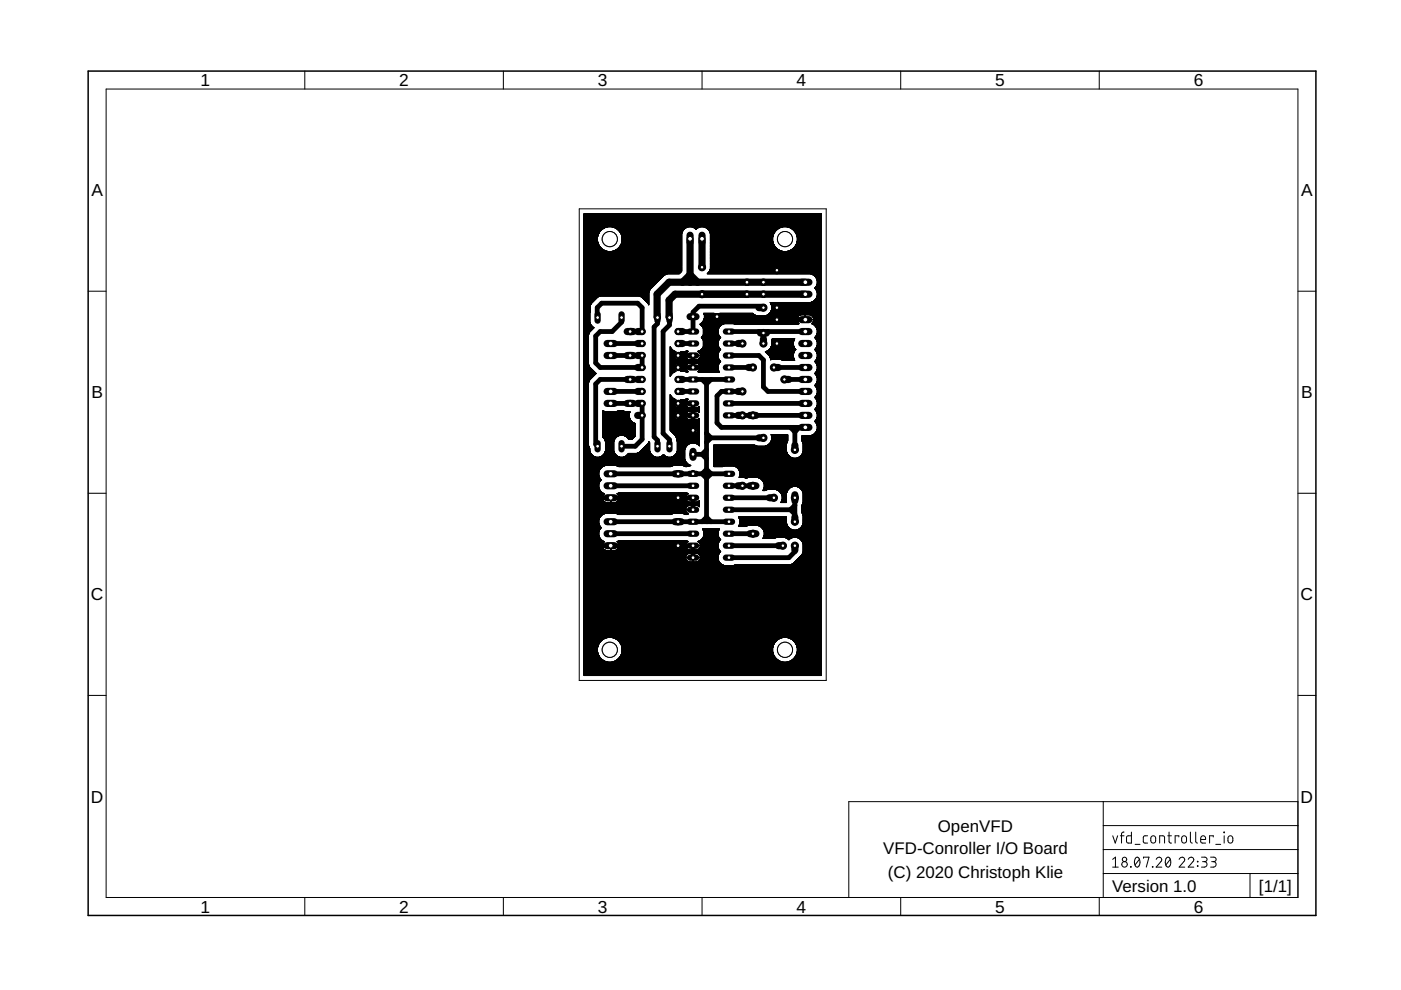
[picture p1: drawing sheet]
<svg xmlns="http://www.w3.org/2000/svg" width="297mm" height="210mm" viewBox="0 0 297 210" stroke-linecap="round" stroke-linejoin="round" font-family="sans-serif">
<defs><g id="words">
<g font-size="3.7">
<text x="42.5" y="18.3">1</text>
<text x="84.7" y="18.3">2</text>
<text x="126.8" y="18.3">3</text>
<text x="168.9" y="18.3">4</text>
<text x="211" y="18.3">5</text>
<text x="253.1" y="18.3">6</text>
<text x="19.4" y="41.6">A</text>
<text x="275.9" y="41.6">A</text>
<text x="19.4" y="84.5">B</text>
<text x="275.9" y="84.5">B</text>
<text x="19.3" y="127.3">C</text>
<text x="275.8" y="127.3">C</text>
<text x="19.3" y="170.2">D</text>
<text x="275.8" y="170.2">D</text>
<text x="42.5" y="193.5">1</text>
<text x="84.7" y="193.5">2</text>
<text x="126.8" y="193.5">3</text>
<text x="168.9" y="193.5">4</text>
<text x="211" y="193.5">5</text>
<text x="253.1" y="193.5">6</text>
</g>
<g font-size="3.6">
<text x="198.8" y="176.3">OpenVFD</text>
<text x="187.3" y="181.1">VFD-Conroller I/O Board</text>
<text x="188.3" y="186.2">(C) 2020 Christoph Klie</text>
<text x="235.8" y="189">Version 1.0</text>
<text x="266.9" y="189">[1/1]</text>
</g>
</g></defs>
<g fill="none" stroke="#000" stroke-width=".51">
<circle cx="129.3" cy="50.7" r=".76"/>
<circle cx="166.4" cy="50.7" r=".76"/>
<circle cx="129.3" cy="137.8" r=".76"/>
<circle cx="166.4" cy="137.8" r=".76"/>
</g>
<g fill="none" stroke="#000" stroke-width="1">
<path d="M164.7 57.3v-.3l-10.8-10.8h-29.6v68.5l1 1h17.8M126.7 67.3l-.1-2.1 1-.9h7.6l.9 .9v5.1M129.5 75.4h3.5M129.5 72.8h5.7M131.8 67.3v1l-2 2h-2.5l-1 .9v5.8l1 .9h7.9M133.9 70.3h1.3M134.2 75.4h1M136.1 75.4v2.5M139.4 67.3v1.3l-.7 .7v23.3l.7 .7v1.3M141.9 67.3v1.6l-1.3 1.4v21.6l1.3 1.3v1.4M144.7 75.4h2.2v2.5M144.7 72.8h2.2"/>
<path d="M151.4 67.8l.6-.7 .7 .7M154.6 70.3h16.2M154.6 75.4h6.3l1 .9v5.7l.9 1h8M154.6 77.9h4.1M154.6 72.8h1.9M160.9 70.3l1 .9M161.9 65.2l-.4-.3h-13.3l-1.3 1.3v4.1h-2.2M161.9 71.2v.7M162.8 70.3l-.9 .9M164.1 67.8h-14l-.6 .6v8.6l-1 .9h-3.8M164.7 66.2v1.6M164.7 66.8l1 1"/>
<path d="M165 77.9h5.8M165.4 67.8h5.4M129.5 85.5h3.5M129.5 83h5.7M133 80.5h-5.7l-1 .9v12.8l.4 .4M134.2 80.5h1M134.2 85.5h1M136.1 85.5v7.7l-1.4 1.4h-2.9M136.1 88.1l.1 .1M144.7 80.5h9.9M144.7 85.5h2.2v5.1M144.7 88.1h2.2"/>
<path d="M144.7 83h2.2M146.9 96.3h1.9M146.9 91.2h-1.5l-1 1v4.1l-1.6 1.6h-18.5M148.8 80.5l1 .9M148.8 96.3l1 1M149.8 81.4v29.2M149.8 99.5l.9 1-.9 .9-1-.9zM149.8 95.4l-1 .9M149.8 91.9l.9 .9M150.7 80.5l-.9 .9M150.7 92.8l-.9 1M150.7 92.8h10.2"/>
<path d="M154.6 88.1h1.9M154.6 85.5h16.2M156.5 83h-3.5l-1 .9v5.8l1 .9h17.8M157.4 88.1h1.6M160.3 88.1h10.5M167.3 80.5h3.5M167.6 90.6l.9 1 1-1M168.2 90.6l.3 .3v3.5M124.3 104.6l1 .9M125.3 105.5h17.8M125.3 105.5l-1 1M129.5 110.6h13.6"/>
<path d="M129.5 100.5h13.6M129.5 103h17.4M129.5 113.2h17.4M144.4 100.5h2.2l.3-.4v.4h7.7M144.4 105.5h2.5v2.6M144.4 115.7h2.5v2.5M144.4 110.6h10.2M148.8 110.6l1-.9 .9 .9M154.6 115.7h10.4M154.6 105.5h8.5M154.6 108.1h13M154.6 103h1.9"/>
<path d="M154.6 113.2h4.4M157.4 103h1.6M167.6 108.1l.9 .9M168.5 116.3v.7l-1.2 1.2h-12.7M168.5 106.2v3.5M168.5 107.1l-.9 1"/>
</g>
<g fill="none" stroke="#000" stroke-width="1.5">
<path d="M144.7 59.8l1.6-1.5 1.6 1.5M146.3 50.6v9.2M148.8 50.6v6.1M170.8 59.8h-28.9l-2.6 2.6 .1 4.9M133 70.3h1.2M133 75.4h1.2M135.2 70.3h.9M135.2 77.9h.9M135.2 75.4h.9M135.2 72.8h.9M143.8 70.3h.9M143.8 77.9h.9"/>
<path d="M143.8 75.4h.9M143.8 72.8h.9M146.3 67.1h1.3M151.4 67.1h1.3M156.5 72.8h.9M158.7 77.9h.9M160.9 65.2h1M161.2 70.6h1.3M161.9 71.9v.9M164.1 77.9h.9M164.1 67.8h1.3M164.7 65.2v1"/>
<path d="M170.8 62.4h-27.7l-1.2 1.2v3.7M133 80.5h1.2M133 85.5h1.2M135.2 80.5h.9M135.2 85.5h.9M135.2 88.1h.9M135.2 83h.9M143.8 80.5h.9M143.8 85.5h.9M143.8 88.1h.9M143.8 83h.9M146.9 90.6v1.3"/>
<path d="M146.9 95.7v1.3M156.5 88.1h.9M156.5 83h.9M159 88.1h1.3M160.9 92.8h1M166.3 80.5h1M168.5 94.4v1M143.1 110.6h1.3M143.1 100.5h1.3M143.1 115.7h1.3M143.1 105.5h1.3M156.5 103h.9"/>
<path d="M159 103h1.3M159 113.2h1.3M163.1 105.5h1M165 115.7h1M168.5 104.9v1.3M168.5 109.7v.9M168.5 115.7v.9"/>
</g>
<g fill="none" stroke="#000" stroke-width=".21">
<path d="M123.8 45.3h50.3v97.9h-50.3zM123.8 53.3h20.7M123.8 57.4h20.7M123.8 57.3h20.7M123.8 57.2h20.7M123.8 57.1h20.7M123.8 57h20.7M123.8 56.9h20.7M123.8 56.8h20.7M123.8 56.7h20.7M123.8 56.6h20.7M123.8 56.5h20.7"/>
<path d="M123.8 56.4h20.7M123.8 56.3h20.7M123.8 56.2h20.7M123.8 56.1h20.7M123.8 56h20.7M123.8 55.9h20.7M123.8 55.8h20.7M123.8 55.7h20.7M123.8 55.6h20.7M123.8 55.5h20.7M123.8 55.4h20.7M123.8 55.3h20.7"/>
<path d="M123.8 55.2h20.7M123.8 55.1h20.7M123.8 55h20.7M123.8 54.9h20.7M123.8 54.8h20.7M123.8 54.7h20.7M123.8 54.6h20.7M123.8 54.5h20.7M123.8 54.4h20.7M123.8 54.3h20.7M123.8 54.2h20.7M123.8 54.1h20.7"/>
<path d="M123.8 54h20.7M123.8 53.9h20.7M123.8 53.8h20.7M123.8 53.7h20.7M123.8 53.6h20.7M123.8 53.5h20.7M123.8 53.4h20.7M123.8 53.3h5M123.8 53.2h4.8M123.8 53.1l4.6 .1M123.8 53.1h4.4M123.8 53l4.3 .1"/>
<path d="M123.8 53h4.3M123.8 52.9l4.2 .1M123.8 52.9h4.1M123.8 52.8l4 .1M123.8 52.8h3.9M123.8 52.7h3.8M123.8 52.6h3.7M123.8 52.5h3.6M123.8 52.4h3.5M123.8 52.3l3.5 .1M123.8 52.3h3.4M123.8 52.2l3.4 .1"/>
<path d="M123.8 52.2h3.3M123.8 52.1l3.3 .1M123.8 52.1h3.3M123.8 52l3.2 .1M123.8 52h3.2M123.8 51.9h3.2M123.8 51.8h3.1M123.8 51.7h3.1M123.8 51.7h3M123.8 51.6h3M123.8 51.5h3M123.8 51.4h3"/>
<path d="M123.8 51.4h2.9M123.8 51.3h2.9M123.8 51.2l2.9 .1M123.8 51.2h2.9M123.8 51.1h2.9M123.8 51h2.9M123.8 50.9h2.9M123.8 50.8h2.9M123.8 50.7h2.9M123.8 50.6h2.9M123.8 50.5h2.9M123.8 50.4h2.9"/>
<path d="M123.8 50.3h2.9M123.8 50.2h2.9M123.8 50.1h2.9M123.8 50h2.9M123.8 49.9h3M123.8 49.8h3M123.8 49.7h3M123.8 49.6h3.1M123.8 48h50.3M123.8 47.9h50.3M123.8 47.8h50.3M123.8 47.7h50.3"/>
<path d="M123.8 47.6h50.3M123.8 47.5h50.3M123.8 47.4h50.3M123.8 47.3h50.3M123.8 47.2h50.3M123.8 47.1h50.3M123.8 47h50.3M123.8 46.9h50.3M123.8 46.8h50.3M123.8 46.7h50.3M123.8 46.6h50.3M123.8 46.5h50.3"/>
<path d="M123.8 46.4h50.3M123.8 46.3h50.3M123.8 46.2h50.3M123.8 46.1h50.3M123.8 46h50.3M123.8 45.9h50.3M123.8 45.8h50.3M123.8 45.7h50.3M123.8 45.6h50.3M123.8 45.5h50.3M123.8 45.4h50.3M126.7 50.4v.7"/>
<path d="M126.7 51.1l.1 .6M126.7 50.3h-2.9M126.7 50.1l-2.9 .1M126.8 50h-3M126.8 49.9h-3M126.8 49.8h-3M126.8 49.7l-.1 .7M126.8 51.7l.4 .6M126.9 49.7h-3.1M126.9 49.6h-3.1M127 49.5h-3.2M127 49.4l-3.2 .1"/>
<path d="M127 49.4h-3.2M127 49.3l-3.2 .1M127.1 49.3h-3.3M127.1 49.2l-3.3 .1M127.1 49.2h-3.3M127.2 49.1h-3.4M127.2 49.1l-.4 .6M127.2 52.3l.5 .5M127.3 49h-3.5M127.4 48.9h-3.6M127.5 48.8h-3.7M127.5 48.7l-3.7 .1"/>
<path d="M127.6 48.7h-3.8M127.6 48.6l-3.8 .1M127.7 48.6l-.5 .5M127.7 52.8l1.2 .5M127.7 48.6h-3.9M127.8 48.5l-4 .1M127.9 48.5h-4.1M128 48.4l-4.2 .1M128.1 48.4h-4.3M128.2 48.3l-4.4 .1M128.2 48.3h-4.4M128.4 48.2l-4.6 .1"/>
<path d="M128.6 48.2h-4.8M128.8 48.1l-5 .1M128.9 48.1l-1.2 .5M129.6 48.1l1.3 .5M129.8 48.1h16.1M129.8 53.3h14.7M130 53.2h14.5M130 48.2h15.7M130.2 48.2h15.4M130.2 53.2h14.3M130.3 53.1h14.2M130.3 48.3h15.2"/>
<path d="M130.4 48.3h15M130.5 53.1h14M130.5 53h14M130.5 48.4h14.8M130.6 48.4h14.6M130.6 53h13.9M130.7 52.9h13.8M130.7 48.5h14.5M130.8 48.5h14.3M130.8 52.9h13.7M130.9 48.6l.8 1.1M130.9 52.8l-1.3 .5"/>
<path d="M130.9 52.8h13.6M130.9 48.6h14.2M130.9 48.6h14.1M131 52.7h13.5M131 48.7h13.9M131.1 52.6h13.4M131.1 48.8h13.7M131.1 48.9h13.7M131.2 52.5h13.3M131.2 48.9h13.6M131.3 49h13.5M131.3 52.4h13.2"/>
<path d="M131.3 49h13.4M131.4 49.1h13.3M131.4 52.3l-.5 .5M131.4 52.3h13.1M131.4 52.2h13.1M131.5 52.2h13M131.5 49.2h13.2M131.5 49.3h13.1M131.5 52.1h13M131.6 49.4h13M131.6 52h12.9M131.6 49.4h12.9"/>
<path d="M131.6 49.5h12.9M131.6 51.9h12.9M131.7 51.8h12.8M131.7 49.6h12.8M131.7 51.7h12.8M131.7 49.7h12.8M131.7 49.7l.2 .7M131.7 51.7l-.3 .6M131.8 51.6h12.7M131.8 49.8h12.7M131.8 51.5h12.7M131.8 49.9h12.7"/>
<path d="M131.8 51.4h12.7M131.8 50h12.7M131.8 51.3h12.7M131.8 50.1h12.7M131.9 51.2h12.6M131.9 50.2h12.6M131.9 51.1h12.6M131.9 50.3h12.6M131.9 50.4v.7M131.9 51.1l-.2 .6M131.9 51h12.6M131.9 50.9h12.6"/>
<path d="M131.9 50.8h12.6M131.9 50.7h12.6M131.9 50.6h12.6M131.9 50.5h12.6M131.9 50.4h12.6M139.2 60h-15.4M139.3 59.9l-15.5 .1M139.3 59.9h-15.5M139.4 59.8l-15.6 .1M139.4 59.8h-15.6M139.5 59.7l-15.7 .1M139.5 59.7h-15.7"/>
<path d="M139.6 59.6h-15.8M139.7 59.5h-15.9M139.8 59.4h-16M139.9 59.3h-16.1M139.9 59.2l-16.1 .1M140 59.2h-16.2M140 59.1l-16.2 .1M140.1 59.1h-16.3M140.1 59l-16.3 .1M140.2 59h-16.4M140.3 58.9h-16.5M140.4 58.8l-2.1 2.1"/>
<path d="M140.4 58.8h-16.6M140.5 58.7h-16.7M140.6 58.6h-16.8M140.6 58.5l-16.8 .1M140.7 58.5h-16.9M140.7 58.4l-16.9 .1M140.8 58.4h-17M140.8 58.3l-.4 .5M140.8 58.3l-17 .1M140.9 58.3h-17.1M141.1 58.2l-17.3 .1M141.2 58.2h-17.4"/>
<path d="M141.4 58.1l-17.6 .1M141.4 58.1h-17.6M141.5 58.1l-.7 .2M144 58l-20.2 .1M144.1 58h-20.3M144.1 57.9l-20.3 .1M144.2 57.9h-20.4M144.2 57.8h-20.4M144.3 57.8h-20.5M144.3 57.7h-20.5M144.4 57.7h-20.6M144.4 57.6h-20.6"/>
<path d="M144.5 57.6h-20.7M144.5 49.5v8M144.5 57.5l-.5 .6M144.5 57.5h-20.7M144.7 49.2h-13.3M144.8 48.9l-.3 .6M145.9 48.1l-.6 .3-.5 .5M146.7 48.1l.9 .5M146.7 48.1h1.7M146.9 48.2h1.4M147 48.2h1.2M147.1 48.3h.9"/>
<path d="M147.2 48.3h.7M147.3 48.4h.5M147.5 48.5h.2M147.6 48.6h.1M147.7 48.5h-.3M147.8 48.4l-.4 .1M148.5 48.1l-.9 .5M149.2 48.1l.6 .3 .5 .5M149.2 48.1h16.7M149.4 48.2h16.3M149.5 48.2h16.1M149.6 48.3h15.8"/>
<path d="M149.8 48.3h15.5M149.9 48.4h15.3M150 58h24.1M150 48.5h14.9M150.1 58h24M150.1 48.6h14.7M150.1 57.9h24M150.2 57.8h23.9M150.2 48.7h14.5M150.3 57.7h23.8M150.3 57.7l-.4 .4 24.2-.1M150.3 48.9l.3 .6v7.5"/>
<path d="M150.3 57.6h23.8M150.3 48.9h14.3M150.4 48.9h14.1M150.4 57.6h23.7M150.4 57.5h23.7M150.4 49h14.1M150.4 49h14M150.4 57.4h23.7M150.5 49.1h13.8M150.5 57.3h23.6M150.5 49.2h13.8M150.5 57.2h23.6"/>
<path d="M150.5 49.3h13.7M150.6 57.1h23.5M150.6 49.4h13.5M150.6 57h23.5M150.6 49.5h13.5M150.6 53.3h23.5M150.6 57l-.3 .7M150.6 56.9h23.5M150.6 56.8h23.5M150.6 56.7h23.5M150.6 56.6h23.5M150.6 56.5h23.5"/>
<path d="M150.6 56.4h23.5M150.6 56.3h23.5M150.6 56.2h23.5M150.6 56.1h23.5M150.6 56h23.5M150.6 55.9h23.5M150.6 55.8h23.5M150.6 55.7h23.5M150.6 55.6h23.5M150.6 55.5h23.5M150.6 55.4h23.5M150.6 55.3h23.5"/>
<path d="M150.6 55.2h23.5M150.6 55.1h23.5M150.6 55h23.5M150.6 54.9h23.5M150.6 54.8h23.5M150.6 54.7h23.5M150.6 54.6h23.5M150.6 54.5h23.5M150.6 54.4h23.5M150.6 54.3h23.5M150.6 54.2h23.5M150.6 54.1h23.5"/>
<path d="M150.6 54h23.5M150.6 53.9h23.5M150.6 53.8h23.5M150.6 53.7h23.5M150.6 53.6h23.5M150.6 53.5h23.5M150.6 53.4h23.5M150.6 53.3h15.3M150.6 53.2h15.2M150.6 53.1l14.9 .1M150.6 53.1h14.8M150.6 53l14.7 .1"/>
<path d="M150.6 53h14.6M150.6 52.9l14.5 .1M150.6 52.9h14.4M150.6 52.8l14.3 .1M150.6 52.8h14.2M150.6 52.7h14.2M150.6 52.7h14.1M150.6 52.6h14.1M150.6 52.6h14M150.6 52.5h13.9M150.6 52.4h13.8M150.6 52.3l13.8 .1"/>
<path d="M150.6 52.3h13.7M150.6 52.2l13.7 .1M150.6 52.2h13.7M150.6 52.1l13.7 .1M150.6 52.1h13.6M150.6 52l13.6 .1M150.6 52h13.5M150.6 51.9l13.5 .1M150.6 51.9h13.5M150.6 51.8h13.5M150.6 51.8h13.4M150.6 51.7l13.4 .1"/>
<path d="M150.6 51.7h13.4M150.6 51.6h13.4M150.6 51.6h13.3M150.6 51.5h13.3M150.6 51.4h13.3M150.6 51.3h13.3M150.6 51.2h13.3M150.6 51.1h13.2M150.6 51h13.2M150.6 50.9h13.2M150.6 50.8h13.2M150.6 50.7h13.2"/>
<path d="M150.6 50.6h13.2M150.6 50.5h13.2M150.6 50.4h13.2M150.6 50.3h13.2M150.6 50.2h13.2M150.6 50.1h13.3M150.6 50h13.3M150.6 49.9h13.3M150.6 49.8h13.4M163.8 50.4v.7M163.8 51.1l.2 .6M163.9 50.2h-13.3"/>
<path d="M163.9 50l-13.3 .1M164 49.7l-.2 .7M164 51.7l.3 .6M164 49.7h-13.4M164 49.6h-13.4M164.1 49.6h-13.5M164.1 49.4l-13.5 .1M164.3 52.3l.5 .5M164.4 49.1h-14M164.6 48.8h-14.3M164.7 48.7l-14.5 .1M164.8 48.6l-.8 1.1"/>
<path d="M164.8 52.8l1.3 .5M165 48.5h-15M165.1 48.4l-15.2 .1M166.1 48.1l-1.3 .5M166.8 48.1l1.2 .5M166.9 48.1h7.2M167 53.3h7.1M167.1 53.2h7M167.2 48.2h6.9M167.3 48.2h6.8M167.3 53.2h6.8M167.5 53.1h6.6"/>
<path d="M167.5 48.3h6.6M167.6 48.3h6.5M167.6 53.1h6.5M167.7 53h6.4M167.7 48.4h6.4M167.8 53h6.3M167.8 52.9h6.3M167.9 48.5h6.2M167.9 52.9h6.2M168 48.6l.9 1.1M168 52.8l-1.2 .5M168 52.8h6.1"/>
<path d="M168 48.6h6.1M168.1 48.6h6M168.1 52.7h6M168.1 48.7h6M168.2 48.7h5.9M168.2 52.6h5.9M168.3 48.8h5.8M168.3 52.5h5.8M168.3 48.9h5.8M168.4 52.5h5.7M168.4 48.9h5.7M168.4 49h5.7"/>
<path d="M168.4 52.4h5.7M168.5 52.4h5.6M168.5 49h5.6M168.5 49.1h5.6M168.5 52.3l-.5 .5M168.5 52.3h5.6M168.6 52.3h5.5M168.6 49.1h5.5M168.6 49.2h5.5M168.6 52.2h5.5M168.6 49.3h5.5M168.7 52.1h5.4"/>
<path d="M168.7 52h5.4M168.7 49.3h5.4M168.7 49.4h5.4M168.7 51.9h5.4M168.8 51.9h5.3M168.8 49.5h5.3M168.8 51.8h5.3M168.8 49.6h5.3M168.8 49.7h5.3M168.9 49.7l.2 .7M168.9 51.7h5.2M168.9 51.6h5.2"/>
<path d="M168.9 49.8h5.2M168.9 49.7h5.2M168.9 51.5h5.2M168.9 49.9h5.2M169 51.5h5.1M169 51.4h5.1M169 50h5.1M169 51.3h5.1M169 50.1h5.1M169 51.2h5.1M169 50.2h5.1M169 51.1h5.1"/>
<path d="M169 50.3h5.1M169.1 50.4v.7M169.1 51.1l-.6 1.2M169.1 51h5M169.1 50.9h5M169.1 50.8h5M169.1 50.7h5M169.1 50.6h5M169.1 50.5h5M169.1 50.4h5M169.1 50.3h5M171.9 58.1l.6 .2"/>
<path d="M171.9 58.1h2.2M172 58.1h2.1M172.2 58.2h1.9M172.3 58.2h1.8M172.4 58.3h1.7M172.5 58.3l.5 .5M172.5 58.3h1.6M172.6 58.4h1.5M172.7 58.5h1.4M172.8 58.6h1.3M172.8 58.7h1.3M172.9 58.7h1.2"/>
<path d="M173 58.8h1.1M173 58.8l.3 .7M173 58.9h1.1M173.1 58.9h1M173.1 59h1M173.1 59.1h1M173.2 59.2h.9M173.2 59.3h.9M173.2 59.4h.9M173.3 59.5h.8M173.3 59.5v.7M173.3 60h.8"/>
<path d="M173.3 59.9h.8M173.3 59.8h.8M173.3 59.7h.8M173.3 59.6h.8M174.1 48.1h-50.3M123.8 71.8h1M123.8 76.4h1M123.8 76.2h1M123.8 67.8h1.2M123.8 67.7h1.2M123.8 66.7h1.2M123.8 68.8h1.4"/>
<path d="M123.8 68.6h1.4M123.8 79h2.4M123.8 77.9h1.3M123.8 77h1M123.8 78.7h2.1M123.8 75.4h1M123.8 76.3h1M123.8 74.6h1M123.8 66.4h1.2M123.8 67.1h1.2M123.8 68.1h1.2M123.8 67h1.2"/>
<path d="M123.8 79.7h2.1M123.8 79.3h2.4M123.8 79.2h2.6M123.8 79.1h2.5M123.8 78.9h2.3M123.8 78.8l2.3 .1M123.8 78.8h2.2M123.8 78.7l2.2 .1M123.8 78.6l2.1 .1M123.8 78.6h2M123.8 78.5l2 .1M123.8 78.5h1.9"/>
<path d="M123.8 78.4h1.8M123.8 78.3l1.7 .1M123.8 78.3h1.7M123.8 78.2l1.7 .1M123.8 78.2h1.6M123.8 78.1h1.5M123.8 78h1.4M123.8 77.8h1.2M123.8 77.7h1.2M123.8 77.6l1.1 .1M123.8 77.6h1.1M123.8 77.5l1.1 .1"/>
<path d="M123.8 77.5h1.1M123.8 77.4h1.1M123.8 77.4h1M123.8 77.3h1M123.8 77.2h1M123.8 77.1h1M123.8 76.9h1M123.8 76.8h1M123.8 76.7h1M123.8 76.6h1M123.8 76.5h1M123.8 76.1h1"/>
<path d="M123.8 76h1M123.8 75.9h1M123.8 75.8h1M123.8 75.7h1M123.8 75.6h1M123.8 75.5h1M123.8 75.3h1M123.8 75.2h1M123.8 75.1h1M123.8 75h1M123.8 74.9h1M123.8 74.8h1"/>
<path d="M123.8 74.7h1M123.8 74.5h1M123.8 74.4h1M123.8 74.3h1M123.8 74.2h1M123.8 74.1h1M123.8 74h1M123.8 73.9h1M123.8 73.8h1M123.8 73.7h1M123.8 73.6h1M123.8 73.5h1"/>
<path d="M123.8 73.4h1M123.8 73.3h1M123.8 73.2h1M123.8 73.1h1M123.8 73h1M123.8 72.9h1M123.8 72.8h1M123.8 72.7h1M123.8 72.6h1M123.8 72.5h1M123.8 72.4h1M123.8 72.3h1"/>
<path d="M123.8 72.2h1M123.8 72.1h1M123.8 72h1M123.8 71.9h1M123.8 71.7h1M123.8 71.6h1M123.8 71.5h1M123.8 71.4h1M123.8 71.3h1M123.8 71.2h1M123.8 71.1h1M123.8 71h1"/>
<path d="M123.8 70.9h1M123.8 70.8h1M123.8 70.7h1.1M123.8 70.6h1.1M123.8 70.5h1.2M123.8 69.4h2.1M123.8 69.4h2M123.8 69.3h1.9M123.8 69.2h1.8M123.8 69.1h1.7M123.8 69l1.7 .1M123.8 69h1.6"/>
<path d="M123.8 68.9l1.5 .1M123.8 68.9h1.5M123.8 68.8h1.5M123.8 68.7h1.4M123.8 68.5h1.3M123.8 68.4h1.3M123.8 68.3h1.3M123.8 68.3h1.2M123.8 68.2h1.2M123.8 68h1.2M123.8 67.9h1.2M123.8 67.6h1.2"/>
<path d="M123.8 67.5h1.2M123.8 67.4h1.2M123.8 67.3h1.2M123.8 67.2h1.2M123.8 66.9h1.2M123.8 66.8h1.2M123.8 66.6h1.2M123.8 66.5h1.2M123.8 66.3h1.2M123.8 66.2h1.3M123.8 66.1h1.3M123.8 66h1.3"/>
<path d="M123.8 65.9h1.3M123.8 65.8h1.3M123.8 65.7h1.3M123.8 65.6h1.3M123.8 65.5h1.3M123.8 65.4h1.3M123.8 65.3h1.3M123.8 65.2h1.3M123.8 65.1h1.3M123.8 65h1.3M123.8 64.9h1.3M123.8 64.8h1.3"/>
<path d="M123.8 64.7h1.4M123.8 64.6h1.4M123.8 62.7h13.7M123.8 62.6h13.7M123.8 62.5h13.7M123.8 62.4h13.7M123.8 62.3h13.7M123.8 62.2h13.7M123.8 62.1h13.7M123.8 62h13.8M123.8 61.8h13.8M123.8 61.7h13.9"/>
<path d="M124.8 71v6.3M124.8 77.3l.2 .5M124.8 70.8l-1 .1M125 70.5h-1.2M125 77.8l1.4 1.4M125 70.4h-1.2M125 66.3v2M125 68.3l.3 .6M125.1 66.3h-1.3M125.1 66.2l-1.3 .1M125.1 64.9v1.3M125.1 66.2l-.1 .1"/>
<path d="M125.1 70.3l-1.3 .1M125.1 70.3h-1.3M125.2 64.7l-1.4 .1M125.2 70.2l-1.4 .1M125.2 64.6l-1.4 .1M125.2 70.2h-1.4M125.3 64.5l-1.5 .1M125.3 68.9l.5 .5M125.3 64.5h-1.5M125.3 70.1h-1.5M125.3 64.4l-1.5 .1M125.3 64.4h-1.5"/>
<path d="M125.4 64.3l-1.6 .1M125.4 70h-1.6M125.4 64.3h-1.6M125.5 70h-1.7M125.5 64.2l-1.7 .1M125.5 69.9h-1.7M125.5 64.2h-1.7M125.6 69.8l-1.8 .1M125.6 64.1l-1.8 .1M125.6 80h-1.8M125.6 69.8h-1.8M125.6 64.1h-1.8"/>
<path d="M125.6 79.9h-1.8M125.7 69.7l-1.9 .1M125.7 64l-1.9 .1M125.7 79.9h-1.9M125.7 69.7h-1.9M125.7 64h-1.9M125.8 79.8h-2M125.8 69.4l.1 .1M125.8 69.6l-2 .1M125.8 63.9h-2M125.8 69.6h-2M125.9 69.5l-2.1 .1"/>
<path d="M125.9 63.8h-2.1M125.9 79.7h-2.1M125.9 69.5l-.9 .9-.2 .6M125.9 69.5h-2.1M126 79.6h-2.2M126 63.7h-2.2M126 79.5l-2.2 .1M126 63.6l-2.2 .1M126.1 79.5h-2.3M126.1 63.6h-2.3M126.1 79.4l-2.3 .1M126.2 63.5l-2.4 .1"/>
<path d="M126.2 79.4h-2.4M126.2 63.5h-2.4M126.3 63.4l-2.5 .1M126.3 79.3h-2.5M126.3 63.4h-2.5M126.3 79.2h-2.5M126.4 63.3l-2.6 .1M126.4 79.2l-1.4 1.4M126.4 63.3h-2.6M126.5 63.2h-2.7M126.6 63.1h-2.8M126.7 63h-2.9"/>
<path d="M126.8 62.9l-3 .1M126.9 62.9h-3.1M127 62.8l-3.2 .1M127.2 62.8h-3.4M127.3 62.8l-.6 .2-1.4 1.4-.2 .5M135.5 62.8l.6 .2 1.4 1.6M135.6 62.8h1.9M135.7 62.8h1.8M135.9 62.9h1.6M136 62.9h1.5M136.1 63h1.4M136.1 63.1h1.4"/>
<path d="M136.2 63.1h1.3M136.2 63.2h1.3M136.3 63.2h1.2M136.3 63.3h1.2M136.4 63.3h1.1M136.4 63.4h1.1M136.5 63.4h1M136.5 63.5h1M136.6 63.5h.9M136.7 63.6h.8M136.8 63.7h.7M136.8 63.8h.7"/>
<path d="M136.9 63.8h.6M136.9 63.9h.6M137 63.9h.5M137 64h.5M137.1 64h.4M137.1 64.1h.4M137.2 64.1h.3M137.2 64.2h.3M137.3 64.2h.2M137.4 64.3h.1M137.4 64.4h.1M137.5 64.4h.1"/>
<path d="M137.5 64.5h.1M137.5 64.6h.1M137.5 62v2.6M137.5 62.7l-13.7 .1M137.6 61.9h-13.8M137.6 61.8h-13.8M137.7 61.7h-13.9M137.7 61.6l-13.9 .1M137.7 61.6h-13.9M137.8 61.5l-14 .1M137.8 61.5h-14M137.8 61.4h-14"/>
<path d="M137.8 61.4l-.3 .6M137.9 61.3h-14.1M138 61.2h-14.2M138.1 61.1h-14.3M138.1 61l-14.3 .1M138.2 61h-14.4M138.2 60.9l-14.4 .1M138.3 60.9h-14.5M138.3 60.9l-.5 .5M138.3 60.8l-14.5 .1M138.4 60.8h-14.6M138.5 60.7l-14.7 .1"/>
<path d="M138.5 60.7h-14.7M138.6 60.6l-14.8 .1M138.6 60.6h-14.8M138.7 60.5l-14.9 .1M138.7 60.5h-14.9M138.8 60.4h-15M138.8 60.3l-15 .1M138.9 60.3h-15.1M138.9 60.2l-15.1 .1M139 60.2h-15.2M139 60.1l-15.2 .1M139.1 60.1h-15.3"/>
<path d="M139.1 60l-15.3 .1M142.1 76.4l10.5 .1M142.1 76.2h1.2M142.1 77.9h10.1M142.1 78.7h1.2M142.1 73.5v6.3l.2-.3M142.1 73.5l.2 .4M142.1 75.4h10.1M142.1 76.3h10.4M142.1 79.3h.3M142.1 79h.6M142.1 78.6l1.1 .1"/>
<path d="M142.1 78.6h1.1M142.1 78.5l1 .1M142.1 78.5h.9M142.1 78.4h.9M142.1 78.3h.8M142.1 78.2h.8M142.1 78.1h.8M142.1 78h.7M142.1 77.9h.7M142.1 77.7h.8M142.1 77.6h.8M142.1 77.5h.8"/>
<path d="M142.1 77.5h.9M142.1 76.6h10.7M142.1 76.5l10.6 .1M142.1 76.5h10.6M142.1 76.4h10.4M142.1 76.3h1.5M142.1 76.2h1.3M142.1 76.1h1.1M142.1 76h1M142.1 75.9l.9 .1M142.1 75.9h.9M142.1 75.8h.9"/>
<path d="M142.1 75.8h.8M142.1 75.7l.8 .1M142.1 75.7h.8M142.1 75.6h.8M142.1 75.5h.8M142.1 75.5h.7M142.1 75.4h.7M142.1 75.3h.7M142.1 75.2h.8M142.1 75.1h.8M142.1 75h.8M142.1 74.9h.9"/>
<path d="M142.1 74.6h1.2M142.1 74.5h1.2M142.1 74.5h1M142.1 74.4h.9M142.1 74.4h.8M142.1 74.3h.6M142.1 74.2h.5M142.1 74.1l.5 .1M142.1 74.1h.4M142.1 74l.4 .1M142.1 74h.3M142.1 73.9l.3 .1"/>
<path d="M142.1 73.9h.2M142.1 73.8h.2M142.1 73.8h.1M142.1 73.7h.1M142.1 73.6h.1M142.1 73.5h.1M142.1 79.8h.1M142.2 79.7h-.1M142.2 79.6h-.1M142.2 79.5l-.1 .1M142.2 79.5h-.1M142.3 73.9l.4 .5 .6 .2"/>
<path d="M142.3 79.4l-.2 .1M142.3 79.4h-.2M142.5 79.3h-.4M142.5 79.2h-.4M142.6 79.2h-.5M142.6 79.1h-.5M142.7 79.1h-.6M142.8 79h-.7M142.8 75.3v.2M142.8 77.8v.2M142.8 78l.1 .2M142.8 75.5l.1 .1"/>
<path d="M142.9 77.8h-.8M142.9 75.2l-.8 .1M142.9 77.7l-.1 .1M142.9 78.2v.2M142.9 75.1l-.1 .2M142.9 75.6v.2M142.9 78.9h-.8M142.9 77.6h-.8M142.9 75l-.8 .1M142.9 77.5v.2M142.9 78.4l.1 .1M142.9 75v.1"/>
<path d="M142.9 75.8l.1 .2M143 77.4h-.9M143 74.9h-.9M143 78.8l-.9 .1M143 74.8l-.9 .1M143 77.3l-.1 .2M143 78.5l.3 .2M143 74.8l-.1 .2M143 76l.7 .3M143 77.3h-.9M143 74.8h-.9M143.1 77.3h-1"/>
<path d="M143.1 74.7l-1 .1M143.2 78.8h-1.1M143.2 77.2h-1.1M143.2 74.7h-1.1M143.3 74.6h-1.2M143.3 77.2h-1.2M143.3 78.7l-.6 .3-.4 .5M143.3 74.6l-.3 .2M143.3 78.7l-1.2 .1M143.3 77.1h4.7M143.3 77.1l-.3 .2M143.3 77.1h-1.2"/>
<path d="M143.5 77l-1.4 .1M143.6 77h-1.5M143.7 76.2h.1M143.7 75.4v.9M143.7 77v.9M143.7 77.9h.1M143.7 77.8h.1M143.7 77.7h.1M143.7 77.6h.1M143.7 77.5h.1M143.7 77.4h.1M143.7 77.3h.1"/>
<path d="M143.7 77.2h.1M143.7 77.1h.1M143.7 77h.1M143.7 76.3h.1M143.7 76.1h.1M143.7 76h.1M143.7 75.9h.1M143.7 75.8h.1M143.7 75.7h.1M143.7 75.6h.1M143.7 75.5h.1M143.7 75.4h.1"/>
<path d="M143.8 75.4v.9M143.8 77v.9M143.8 77l.4 .1M143.9 76.3h2.2M144.1 77h1.9M144.1 76.2h1.8M144.2 77.1l.3 .2M144.2 77.1h1.6M144.2 76.2h1.6M144.3 77.2h1.5M144.3 78.7h1.5M144.3 76.1h1.5"/>
<path d="M144.4 77.2h1.3M144.4 74.7h1.3M144.4 78.6h1.3M144.4 76.1h1.3M144.4 78.6h1.2M144.4 77.3h1.2M144.4 76h1.2M144.4 74.7h1.2M144.5 78.5l-.2 .2h1.5M144.5 77.3l.2 .4M144.5 76l-.7 .3M144.5 74.8l.2 .3"/>
<path d="M144.5 78.5h1.1M144.5 76h1.1M144.5 78.5h1M144.5 77.4h1M144.5 74.8h1M144.5 75.9h1M144.5 78.4h1M144.5 74.9h1M144.6 77.5h.9M144.6 75.8h.9M144.6 74.9h.9M144.6 78.4l-.1 .1"/>
<path d="M144.6 75.8l-.1 .2M144.6 78.3l.9 .1M144.6 78.3h.8M144.6 75.7l.8 .1M144.6 78.2l.8 .1M144.6 75.7h.8M144.7 75.1v.5M144.7 77.7v.5M144.7 78.2l-.1 .2M144.7 75.6l-.1 .2M144.7 78.2h.7M144.7 78.1h.7"/>
<path d="M144.7 77.7h.7M144.7 77.6h.7M144.7 75.6h.7M144.7 75.1h.7M144.7 78h.7M144.7 77.8h.7M144.7 75.5h.7M144.7 75.2h.7M144.7 77.9h.7M144.7 75.4h.7M144.7 75.3h.7M145.1 78.7l.5 .2"/>
<path d="M145.2 78.7l.7 .1M145.3 78.8h.6M145.4 75.3v.2M145.4 77.8v.2M145.4 78v.2M145.4 75.5v.1M145.4 74.5h.5M145.4 77.7v.1M145.4 78.2l.1 .2M145.4 75.1v.2M145.4 75.6l.1 .2M145.4 77.6h-.8"/>
<path d="M145.4 75l-.8 .1M145.4 77.5l-.8 .1M145.4 75h-.8M145.5 78.4l.1 .1M145.5 75.8l.1 .2M145.5 78.8h.3M145.5 74.4h.3M145.6 77.3l-.2 .4M145.6 78.5l.3 .3M145.6 74.8l-.2 .3M145.6 76l.6 .3M145.6 77.3h-1.1"/>
<path d="M145.6 74.8h-1.1M145.6 78.9h.1M145.6 74.4l-.5 .2M145.6 74.4l.3 .1M145.6 74.4h.1M145.8 74.6h-1.5l.2 .2M145.8 77.1l-.2 .2M145.8 74.6l-.2 .2M145.8 74.6h-.7M145.9 78.8h.1M145.9 78.8l-.3 .1M145.9 74.5h.1"/>
<path d="M145.9 74.5l-.1 .1M145.9 74.5h-.7M146.2 77l-.4 .1M146.9 76.2h.1M146.9 75.4v.9M146.9 77v.9M146.9 77.9h.1M146.9 77.8h.1M146.9 77.7h.1M146.9 77.6h.1M146.9 77.5h.1M146.9 77.4h.1"/>
<path d="M146.9 77.3h.1M146.9 77.2h.1M146.9 77.1h.1M146.9 77h.1M146.9 76.3h.1M146.9 76.1h.1M146.9 76h.1M146.9 75.9h.1M146.9 75.8h.1M146.9 75.7h.1M146.9 75.6h.1M146.9 75.5h.1"/>
<path d="M146.9 75.4h.1M147 75.4v.9M147 77v.9M147.7 77h4.8M147.8 76.3h4.7M147.9 77h4.5M147.9 78.8l.4 .2 4.2-.1M147.9 78.8h4.6M147.9 74.5l.1 .1M147.9 74.5h.1M147.9 78.8h4.5M147.9 76.2h4.5"/>
<path d="M147.9 74.5h4.5M148 74.5h4.5M148 77.1l.3 .2M148 74.6l.3 .2M148 77.1h4.4M148 74.6h4.4M148.1 78.8l4.4 .1M148.1 76.2h4.3M148.1 78.7h4.3M148.1 74.6h4.3M148.1 77.2h4.3M148.1 76.1h4.3"/>
<path d="M148.2 77.2h4.2M148.2 74.7h4.2M148.2 78.6h4.2M148.2 76.1h4.2M148.2 78.9h4.3M148.3 78.6h4.1M148.3 77.3h4.1M148.3 76h4.1M148.3 74.7h4.1M148.3 78.5l-.4 .3M148.3 77.3l.1 .2M148.3 76l-.6 .3"/>
<path d="M148.3 74.8l.1 .2M148.3 78.5h4M148.3 77.3h4M148.3 76h4M148.3 74.8h4M148.3 77.4h4M148.4 78.4h3.9M148.4 75.9h3.9M148.4 77.4h3.9M148.4 74.9h3.9M148.4 77.5h3.9M148.4 75.8l3.9 .1"/>
<path d="M148.4 78.4l-.1 .1M148.4 77.5l.1 .2M148.4 75.8l-.1 .2M148.4 75l.1 .1M148.4 78.3l3.9 .1M148.4 75.8h3.9M148.4 78.3h3.9M148.5 68.9l.5 .5M148.5 68.7v.2M148.5 78.2h3.7M148.5 77.6h3.7M148.5 75.7h3.7"/>
<path d="M148.5 75h3.7M148.5 78.2l-.1 .2M148.5 77.7v.1M148.5 75.6l-.1 .2M148.5 75.1v.2M148.5 77.7h3.7M148.5 75.6h3.7M148.5 75.1h3.7M148.5 78.1h3.7M148.5 77.8h3.7M148.5 75.5h3.7M148.5 75.2h3.7"/>
<path d="M148.5 75.3v.2M148.5 77.8v.2M148.5 78v.2M148.5 75.5v.1M148.5 78h3.7M148.5 77.9h3.7M148.5 75.4h3.7M148.5 75.3h3.7M148.5 68.9h4.5M148.6 68.9h4.3M148.6 68.6h20.8M148.7 69h4.1"/>
<path d="M148.7 68.6h20.6M148.7 71.6l.3 .3M148.7 71.6h4.1M148.7 68.5h20.6M148.7 74.1h4.1M148.7 71.5h4.1M148.8 71.6h3.9M148.8 69.1h3.9M148.8 68.5h20.4M148.8 74h3.9M148.8 71.7h3.9M148.8 71.5h3.9"/>
<path d="M148.8 69.2h3.9M148.8 68.4h20.4M148.8 71.4h3.8M148.9 71.8h3.7M148.9 69.2h3.7M148.9 68.3h20.2M148.9 73.9h3.7M148.9 71.4h3.7M148.9 69.3h3.7M148.9 73.9h3.6M148.9 71.3h3.6M149 71.9h3.5"/>
<path d="M149 69.3h3.5M149 68.2h20.1M149 73.8h3.5M149 73.8l-.5 .5-.6 .2M149 71.9l.3 .6M149 71.2l-.3 .4M149 69.4l.3 .6M149 71.2h3.5M149 69.4h3.5M149 73.7h3.5M149 72h3.4M149 69.4h3.4"/>
<path d="M149 68.2h20M149.1 73.7h3.3M149.1 72h3.3M149.1 71.1h3.3M149.1 69.5h3.3M149.1 68.1l-.6 .6M149.1 73.6h3.3M149.1 72.1h3.3M149.1 68.1h19.9M149.1 71h3.3M149.1 69.6h3.3M149.1 73.5h3.3"/>
<path d="M149.1 68h2.5M149.1 72.2h3.2M149.1 72.2h3.3M149.1 70.9h3.2M149.1 69.7h3.2M149.2 73.4h3.1M149.2 70.9h3.1M149.2 67.9h2.3M149.2 72.3h3.1M149.2 70.8h3.1M149.2 69.8h3.1M149.2 69.7h3.1"/>
<path d="M149.2 67.9h2.2M149.2 67.8h2.2M149.2 73.3h3.1M149.2 66.4h2.2M149.2 67.8h2.1M149.2 66.5h2.1M149.2 73.2h3.1M149.2 70.7h3.1M149.2 70.7h3M149.2 67.7h2.1M149.3 73.2l-.3 .6M149.3 70v.6"/>
<path d="M149.3 72.5v.7M149.3 70.6l-.3 .6M149.3 73.1h2.9M149.3 73h2.9M149.3 72.9h2.9M149.3 72.8h2.9M149.3 72.7h2.9M149.3 72.6h2.9M149.3 72.5h2.9M149.3 70.6h2.9M149.3 70.5h2.9M149.3 70.4h2.9"/>
<path d="M149.3 70.3h2.9M149.3 70.2h2.9M149.3 70.1h2.9M149.3 70h2.9M149.3 67.6h1.9M149.3 66.6h1.9M149.3 66.7h1.9M149.3 67.5h1.8M149.3 66.8h1.8M149.4 67.1h19.8M149.4 67h1.7M149.4 67.4h1.7"/>
<path d="M149.4 67.3h1.7M149.4 67.2h1.7M149.4 66.9h1.7M149.4 66.8h1.7M151.1 66.7h-1.8M151.6 68.1l-.5-.6v-.8l.3-.3h-2.2l.2 1.1-.3 .6M152 67.8h.1M152 67.7h.1M152 67.1v1M152 68h.1M152 67.9h.1M152 67.6h.1"/>
<path d="M152 67.5h.1M152 67.4h.1M152 67.3h.1M152 67.2h.1M152.2 70v.6M152.2 72.5v.7M152.2 75.1v.6M152.2 77.6v.7M152.2 70.6l.3 .6M152.2 73.2l.3 .6M152.2 75.7l.3 .6M152.2 78.3l.3 .6"/>
<path d="M152.3 77.5l-3.9 .1M152.3 75h-3.9M152.3 72.4l-3.1 .1M152.3 69.9h-3.1M152.3 72.4h-3.1M152.3 69.8l-3.1 .1M152.4 68h16.6M152.5 69.4l-.3 .6M152.5 71.2l.3 .4M152.5 71.9l-.3 .6M152.5 73.8l.3 .3M152.5 74.4l-.3 .7"/>
<path d="M152.5 76.3l.3 .3M152.5 77l-.3 .6M152.5 68h16.5M152.5 76.9l-10.4 .1M152.5 74.4h-4.4M152.5 67.9h16.5M152.6 76.9h-10.5M152.6 74.4h-4.4M152.6 67.9h16.4M152.6 76.8l-10.5 .1M152.6 74.3h-4.2M152.6 66.4l7.1 .1"/>
<path d="M152.7 76.8h-10.6M152.7 74.3h-4.2M152.7 67.8h21.4M152.7 66.5h7M152.7 76.7l-10.6 .1M152.7 74.2h-4.1M152.7 67.7h16.3M152.7 66.5l7.1 .1M152.8 76.7h-10.7M152.8 74.1l-4.2 .1M152.8 71.6l-.3 .3M152.8 74.1l-.3 .3"/>
<path d="M152.8 76.6l-.3 .4M152.8 74.1h-4.1M152.8 66.6h7M152.8 67.6h16.2M152.8 66.7h7.1M152.9 66.7h7M153 67h16.3M153 67.5h16M153 66.9l7.5 .1M153 66.9h7.3M153 66.8l7.2 .1M153 66.8h7.1"/>
<path d="M153.1 68.8l-4.6 .1M153.2 68.8h-4.7M153.3 68.7l-4.8 .1M153.4 68.7h-4.9M153.6 68.6l-.6 .3-.5 .5M155.6 68.6l.3 .2h13.1l.4-.2M155.7 68.7h13.5M155.8 68.7h13.4M159.9 66.7l-.3-.3h-7l.4 .3v.8l-.6 .6M159.9 66.7l.6 .3M162.3 74.6l.9 .9M162.3 74.6h6.1"/>
<path d="M162.3 74.7h6.1M162.4 74.7h5.9M162.5 74.8h5.8M162.5 74.5h5.9M162.6 74.9h5.7M162.7 75h5.5M162.8 75.1h5.4M162.8 66.7h11.3M162.9 66.7l-.7 .3M162.9 75.2h5.3M162.9 66.7h11.2M162.9 74.3h5.7"/>
<path d="M162.9 66.6h11.2M163 75.3h5.2M163 66.6h11.1M163 75.4h5.2M163.1 74.1h5.6M163.1 66.5h11M163.1 75.4h5.1M163.1 75.5h5.1M163.2 75.5l.2 .5M163.2 66.4h10.9M163.2 75.6h5M163.2 75.5h5"/>
<path d="M163.2 74h5.5M163.2 75.7h5M163.3 75.7h4.9M163.3 73.9l5.3 .1M163.3 66.3h10.8M163.3 75.8h5M163.3 73.9h5.3M163.3 75.9h5M163.3 64.2h10.8M163.3 75.9l5 .1M163.4 73.9l-.5 .5-.6 .2M163.4 64.2l.2 .7"/>
<path d="M163.4 76h4.9M163.4 73.8l5.1 .1M163.4 73.8h5.1M163.4 66.2h10.7M163.4 64.2h10.7M163.4 76.2h5M163.4 76v.3M163.4 76.1h5M163.4 64.3h10.7M163.4 73.7h5M163.4 66.1h10.7M163.4 64.4h10.7"/>
<path d="M163.4 73.6h5M163.4 66h10.7M163.5 76.3h-.1M163.5 73.6h4.9M163.5 66h10.6M163.5 64.5h10.6M163.5 73.5h4.9M163.5 65.9h10.6M163.5 73.5h4.8M163.5 65.8h10.6M163.5 64.6h10.6M163.5 73.4h4.8"/>
<path d="M163.6 73.4h4.7M163.6 65.7h10.5M163.6 64.7h10.5M163.6 73.3h4.7M163.6 65.6h10.5M163.6 64.8h10.5M163.6 76.2h-.2M163.6 73.2h4.6M163.6 64.9h10.5M163.6 73.2l-.2 .7M163.6 64.9v.7M163.6 72v1.2"/>
<path d="M163.6 65.6l-.2 .6-.5 .5M163.6 73.1h4.6M163.6 73h4.6M163.6 72.9h4.6M163.6 72.8h4.6M163.6 72.7h4.6M163.6 72.6h4.6M163.6 72.5h4.6M163.6 72.3h4.7M163.6 72.2h4.7M163.6 72.1h4.8M163.6 72h4.8"/>
<path d="M163.6 65.5h10.5M163.6 65.4h10.5M163.6 65.3h10.5M163.6 65.2h10.5M163.6 65.1h10.5M163.6 65h10.5M163.7 71.9h4.7M163.7 76.2l-.3 .1M163.7 71.9h4.8M165.4 76.2l.6 .2h2.5M165.5 76.2h2.9M165.7 76.3h2.7"/>
<path d="M165.8 76.3h2.7M165.9 76.4h2.6M168.2 72.5v.7M168.2 75v.7M168.2 73.2l.3 .7M168.2 75.7l.3 .7M168.2 72.4l-4.6 .1M168.3 72.4h-4.7M168.3 72.3l-4.7 .1M168.3 72.2l-4.7 .1M168.4 72.1l-4.8 .1M168.4 74.6h-6.1"/>
<path d="M168.4 74.5h-6M168.5 74.4h-5.9M168.5 71.8h-4.7l-.2 .2M168.5 71.8h.1M168.5 71.8l-.3 .7M168.5 73.9l.2 .2M168.5 74.4l-.3 .6M168.5 74.4h-5.7M168.6 74.3h-5.7M168.7 74.2h-5.7M168.7 74.1l-5.7 .1M168.7 74.1l-.2 .3"/>
<path d="M169 67.7v.2M169 67.9v.2M169 67.6h-16.2M169 67.5v.2M169 68.1l.1 .2M169 67.5h-16.1M169 67.4h-16M169.1 67.3h-16.1M169.1 67.3l-.1 .2M169.1 68.3l.2 .3M169.1 67.2l-16.1 .1M169.1 67.2h-16.1"/>
<path d="M169.2 67.1l-.1 .2M169.2 67l-16.2 .1M169.3 68.6h.1M169.4 68.6l-20.9 .1M169.4 66.9l-7.1 .1M169.5 66.9h-7.1M169.6 66.8l-7.1 .1M169.8 66.8h-7.1M169.9 66.7l-.7 .4M170.7 66.7v1.1M170.7 67.1h.1M170.7 67h.1"/>
<path d="M170.7 67.7h.1M170.7 67.6h.1M170.7 67.5h.1M170.7 67.4h.1M170.7 67.3h.1M170.7 67.2h.1M170.7 66.9h.1M170.7 66.8h.1M171.6 66.7l.7 .4M171.7 66.8h2.4M171.9 66.8h2.2M172 64.1h2.1"/>
<path d="M172 66.9h2.1M172.1 68.6l.4 .2 .5 .5 .3 .7M172.1 68.6h2M172.1 64.1h2M172.1 66.9h2M172.2 68.6h-.1M172.2 68.6h1.9M172.2 67h1.9M172.2 68.7h1.9M172.2 68.5h1.9M172.2 64h1.9M172.3 68.5h1.8"/>
<path d="M172.3 67.1l.1 .2M172.3 67.1h1.8M172.3 68.4h1.8M172.3 68.7h1.8M172.3 63.9h1.8M172.4 68.3h1.7M172.4 67.2h1.7M172.4 68.3l-.2 .3M172.4 67.3l.1 .2M172.4 68.2h1.7M172.4 67.3h1.7M172.4 67.4h1.7"/>
<path d="M172.5 68.1h1.6M172.5 68.1l-.1 .2M172.5 67.5v.2M172.5 68.8h1.6M172.5 67.5h1.6M172.5 67.4h1.6M172.5 63.9h1.6M172.5 68h1.6M172.5 67.6h1.6M172.5 67.9v.2M172.5 67.7v.2M172.5 67.9h1.6"/>
<path d="M172.5 67.8h1.6M172.5 67.7h1.6M172.5 63.8h1.6M172.6 68.9h1.5M172.6 63.8h1.5M172.7 68.9h1.4M172.7 63.7h1.4M172.7 69h1.4M172.7 63.6h1.4M172.7 79.2l.3 .3M172.7 76.6l.3 .3M172.7 74.1l.6 .9"/>
<path d="M172.7 71.6l.6 .9M172.7 61.1l.3 .3M172.7 79.2h1.4M172.7 76.6h1.4M172.7 74.1h1.4M172.8 71.6h1.3M172.8 69h1.3M172.8 63.6h1.3M172.8 61.1h1.3M172.8 79.2h1.3M172.8 79.1h1.3M172.8 76.7h1.3"/>
<path d="M172.8 76.6h1.3M172.8 74.1h1.3M172.8 71.5h1.3M172.8 61.2h1.3M172.8 79.3h1.3M172.8 74.2h1.3M172.8 69.1h1.3M172.8 61h1.3M172.8 76.5h1.3M172.8 74h1.3M172.8 71.7h1.3M172.8 69.2h1.3"/>
<path d="M172.8 63.5h1.3M172.9 79.3h1.2M172.9 76.8h1.2M172.9 74.3h1.2M172.9 79h1.2M172.9 76.5h1.2M172.9 73.9h1.2M172.9 71.8h1.2M172.9 71.4h1.2M172.9 69.2h1.2M172.9 63.5h1.2M172.9 61.3h1.2"/>
<path d="M172.9 60.9h1.2M172.9 79.4h1.2M173 71.8h1.1M173 74.4h1.1M173 71.3h1.1M173 69.3h1.1M173 63.4h1.1M173 61.3h1.1M173 60.9h1.1M173 79.4h1.1M173 78.9h1.1M173 76.9h1.1"/>
<path d="M173 76.4h1.1M173 73.9h1.1M173 79.5l.3 .6M173 78.9l-.3 .3M173 76.9l.3 .7M173 76.4l-.3 .2M173 73.9l-.3 .2M173 71.3l-.3 .3M173 76.3h1.1M173 61.4l.3 .6M173 79.5h1.1M173 73.8h1.1"/>
<path d="M173 71.9h1.1M173 63.3h1.1M173 61.4h1.1M173 60.8h1.1M173 74.5h1.1M173 71.2h1.1M173 69.4h1.1M173 60.7h1.1M173.1 77h1M173.1 79.5h1M173.1 78.8h1M173.1 76.3h1"/>
<path d="M173.1 74.5h1M173.1 73.7h1M173.1 72h1M173.1 71.2h1M173.1 69.4h1M173.1 63.2h1M173.1 61.5h1M173.1 60.7h1M173.1 79.6h1M173.1 78.7h1M173.1 77.1h1M173.1 76.2h1"/>
<path d="M173.1 74.6h1M173.1 71.1h1M173.1 69.5h1M173.1 60.6h1M173.1 79.7h1M173.1 77.2h1M173.1 73.6h1M173.1 72.1h1M173.1 63.1h1M173.1 61.6h1M173.1 79.8h1M173.1 78.6h1"/>
<path d="M173.1 76.1h1M173.1 74.7h1M173.1 71h1M173.1 69.6h1M173.1 60.5h1M173.1 77.3h1M173.1 73.5h1M173.1 72.2h1M173.1 63h1M173.1 61.7h1M173.2 79.8h.9M173.2 78.5h.9"/>
<path d="M173.2 76h.9M173.2 73.5h.9M173.2 72.2h.9M173.2 70.9h.9M173.2 69.7h.9M173.2 63h.9M173.2 61.7h.9M173.2 79.9h.9M173.2 77.4h.9M173.2 77.3h.9M173.2 75.9h.9M173.2 74.8h.9"/>
<path d="M173.2 73.4h.9M173.2 72.3h.9M173.2 62.9h.9M173.2 61.8h.9M173.2 60.4h.9M173.2 78.4h.9M173.2 70.8h.9M173.2 69.8h.9M173.2 80h.9M173.2 77.5h.9M173.2 75.8h.9M173.2 74.9h.9"/>
<path d="M173.2 73.3h.9M173.2 72.4h.9M173.2 62.8h.9M173.2 61.9h.9M173.2 60.3h.9M173.2 78.3h.9M173.2 70.7h.9M173.2 69.9h.9M173.2 62h.9M173.3 78.3h.8M173.3 77.5h.8M173.3 75.8h.8"/>
<path d="M173.3 75h.8M173.3 73.2h.8M173.3 70.7h.8M173.3 62h.8M173.3 60.2h.8M173.3 62v.7M173.3 70v.7M173.3 72.5v.7M173.3 75v.7M173.3 77.6v.7M173.3 78.3l-.3 .6M173.3 75.7l-.3 .7"/>
<path d="M173.3 73.2l-.3 .7M173.3 70.7l-.3 .6M173.3 77.9h.8M173.3 75.4h.8M173.3 62.7l-.3 .7-.5 .5-.6 .2M173.3 60.2l-.6 .9M173.3 78.2h.8M173.3 78.1h.8M173.3 78h.8M173.3 77.8h.8M173.3 77.7h.8M173.3 77.6h.8"/>
<path d="M173.3 75.7h.8M173.3 75.6h.8M173.3 75.5h.8M173.3 75.3h.8M173.3 75.2h.8M173.3 75.1h.8M173.3 73.1h.8M173.3 73h.8M173.3 72.9h.8M173.3 72.8h.8M173.3 72.7h.8M173.3 72.6h.8"/>
<path d="M173.3 72.5h.8M173.3 70.6h.8M173.3 70.5h.8M173.3 70.4h.8M173.3 70.3h.8M173.3 70.2h.8M173.3 70.1h.8M173.3 70h.8M173.3 62.7h.8M173.3 62.6h.8M173.3 62.5h.8M173.3 62.4h.8"/>
<path d="M173.3 62.3h.8M173.3 62.2h.8M173.3 62.1h.8M173.3 60.1h.8M174.1 67.8h-21.5M174.1 64.2l-10.8-.1 .1 .1M123.8 92.2h1M123.8 91.2h1M123.8 90.3h1M123.8 88.1h1M123.8 87.1h1M123.8 89h1"/>
<path d="M123.8 92.4h1M123.8 96.9l21.4 .1M123.8 87.3h1M123.8 87h1M123.8 93.1h1M123.8 92.3h1M123.8 96.1h1.5M123.8 85.5h1M123.8 86.4h1M123.8 84.7h1M123.8 93.9h1M123.8 94.3h1"/>
<path d="M123.8 94.6h1M123.8 92.1h1M123.8 97.1h21.4M123.8 99.9h3.2M123.8 99.8h3.3M123.8 99.7h3.3M123.8 99.6h3.3M123.8 99.5h3.4M123.8 99.3h3.6M123.8 99h3.9M123.8 98.6l22.6 .1M123.8 98.6h22.4"/>
<path d="M123.8 98.5l22.3 .1M123.8 98.5h22.2M123.8 98.4h22.1M123.8 98.3h22M123.8 98.3h21.9M123.8 98.2h21.9M123.8 98.1l21.8 .1M123.8 98.1h21.8M123.8 98l21.7 .1M123.8 98h21.7M123.8 97.9l21.6 .1M123.8 97.9h21.6"/>
<path d="M123.8 97.8l21.6 .1M123.8 97.8h21.6M123.8 97.7h21.6M123.8 97.7h21.5M123.8 97.6h21.5M123.8 97.5h21.4M123.8 97.4h21.4M123.8 97.3h21.4M123.8 97.2h21.4M123.8 97h21.4M123.8 96.9h2.5M123.8 96.8l2.4 .1"/>
<path d="M123.8 96.8h2.2M123.8 96.7l2.1 .1M123.8 96.7h2M123.8 96.6h1.9M123.8 96.6h1.8M123.8 96.5h1.8M123.8 96.4h1.7M123.8 96.4h1.6M123.8 96.3h1.6M123.8 96.2l1.5 .1M123.8 96.2h1.5M123.8 96.1h1.4"/>
<path d="M123.8 96h1.4M123.8 95.9h1.4M123.8 95.8h1.3M123.8 95.7h1.3M123.8 95.6h1.3M123.8 95.5h1.2M123.8 95.4h1.2M123.8 95.3h1.2M123.8 95.2h1.2M123.8 95.1h1.2M123.8 95h1.2M123.8 94.9h1.2"/>
<path d="M123.8 94.9h1.1M123.8 94.8h1.1M123.8 94.7h1.1M123.8 94.5h1M123.8 94.4h1M123.8 94.2h1M123.8 94.1h1M123.8 94h1M123.8 93.8h1M123.8 93.7h1M123.8 93.6h1M123.8 93.5h1"/>
<path d="M123.8 93.4h1M123.8 93.3h1M123.8 93.2h1M123.8 93h1M123.8 92.9h1M123.8 92.8h1M123.8 92.7h1M123.8 92.6h1M123.8 92.5h1M123.8 92h1M123.8 91.9h1M123.8 91.8h1"/>
<path d="M123.8 91.7h1M123.8 91.6h1M123.8 91.5h1M123.8 91.4h1M123.8 91.3h1M123.8 91.1h1M123.8 91h1M123.8 90.9h1M123.8 90.8h1M123.8 90.7h1M123.8 90.6h1M123.8 90.5h1"/>
<path d="M123.8 90.4h1M123.8 90.2h1M123.8 90.1h1M123.8 90h1M123.8 89.9h1M123.8 89.8h1M123.8 89.7h1M123.8 89.6h1M123.8 89.5h1M123.8 89.4h1M123.8 89.3h1M123.8 89.2h1"/>
<path d="M123.8 89.1h1M123.8 88.9h1M123.8 88.8h1M123.8 88.7h1M123.8 88.6h1M123.8 88.5h1M123.8 88.4h1M123.8 88.3h1M123.8 88.2h1M123.8 88h1M123.8 87.9h1M123.8 87.8h1"/>
<path d="M123.8 87.7h1M123.8 87.6h1M123.8 87.5h1M123.8 87.4h1M123.8 87.2h1M123.8 86.9h1M123.8 86.8h1M123.8 86.7h1M123.8 86.6h1M123.8 86.5h1M123.8 86.3h1M123.8 86.2h1"/>
<path d="M123.8 86.1h1M123.8 86h1M123.8 85.9h1M123.8 85.8h1M123.8 85.7h1M123.8 85.6h1M123.8 85.4h1M123.8 85.3h1M123.8 85.2h1M123.8 85.1h1M123.8 85h1M123.8 84.9h1"/>
<path d="M123.8 84.8h1M123.8 84.6h1M123.8 84.5h1M123.8 84.4h1M123.8 84.3h1M123.8 84.2h1M123.8 84.1h1M123.8 84h1M123.8 83.9h1M123.8 83.8h1M123.8 83.7h1M123.8 83.6h1"/>
<path d="M123.8 83.5h1M123.8 83.4h1M123.8 83.3h1M123.8 83.2h1M123.8 83.1h1M123.8 83h1M123.8 82.9h1M123.8 82.8h1M123.8 82.7h1M123.8 82.6h1M123.8 82.5h1M123.8 82.4h1"/>
<path d="M123.8 82.3h1M123.8 82.2h1M123.8 82.1h1M123.8 82h1M123.8 81.9h1M123.8 81.8h1M123.8 81.7h1M123.8 81.6h1M123.8 81.5h1M123.8 81.4h1M123.8 81.3h1M123.8 81.2h1"/>
<path d="M123.8 81.1h1M123.8 80.7h1.2M123.8 80.6h1.2M123.8 80.3h1.4M123.8 80h1.7M124.8 81.1v13.4M124.8 94.5l.2 .6M124.8 81.1h-1M124.8 81h-1M124.9 80.9l-1.1 .1M124.9 80.9h-1.1M124.9 80.8l-1.1 .1"/>
<path d="M124.9 80.8h-1.1M124.9 80.7l-1.1 .1M125 80.6h-1.2M125 80.6l-.2 .5M125 95.1v.5M125 95.6l.3 .6M125.1 80.5h-1.3M125.2 80.4h-1.4M125.3 96.2l.5 .5 .6 .2M125.3 80.3h-1.5M125.3 80.2l-1.5 .1M125.4 80.2h-1.6"/>
<path d="M125.4 80.1l-1.6 .1M125.5 80.1h-1.7M127 99.9l-3.2 .1M127 99.8l-3.2 .1M127.1 99.7l-3.3 .1M127.1 96.9h4.2M127.3 99.4h-3.5M127.3 96.9h4M127.4 99.3h-3.6M127.4 96.8h3.7M127.5 99.2l-3.7 .1M127.5 99.2h-3.7"/>
<path d="M127.5 96.8h3.5M127.6 99.1h-3.8M127.7 96.7l-.7 .2M127.7 96.7h3.1M127.7 99h-3.9M127.7 96.6h3.1M127.7 99l-.5 .5-.3 .6M127.8 96.6h2.9M127.8 96.5h2.9M127.8 92.2h6.8M127.8 91.2h6.8M127.8 90.3h6.8"/>
<path d="M127.8 88.1h5.6M127.8 87.1l.2 .1M127.8 89h5.8M127.8 92.7l.3 .3M127.8 87.1v5.6M127.8 87.1l.6 .2M127.8 87.3h5.8l-.2 .4M127.8 92.1h6.8M127.8 92h6.8M127.8 91.9h6.8M127.8 91.8h6.8M127.8 91.7h6.8"/>
<path d="M127.8 91.6h6.8M127.8 91.5h6.8M127.8 91.4h6.8M127.8 91.3h6.8M127.8 91.1h6.8M127.8 91h6.8M127.8 90.9h6.8M127.8 90.8h6.8M127.8 90.7h6.8M127.8 90.6h6.8M127.8 90.5h6.8M127.8 90.4h6.8"/>
<path d="M127.8 90.2h6.8M127.8 90.1h6.8M127.8 90h6.8M127.8 89.9h6.8M127.8 89.8h6.8M127.8 89.7h6.8M127.8 89.7h6.7M127.8 89.6h6.5M127.8 89.6h6.4M127.8 89.5h6.3M127.8 89.4h6.2M127.8 89.3l6.2 .1"/>
<path d="M127.8 89.3h6.1M127.8 89.2l6.1 .1M127.8 89.2h6M127.8 89.1l6 .1M127.8 89.1h5.9M127.8 89l5.9 .1M127.8 88.9l5.8 .1M127.8 88.9h5.8M127.8 88.8l5.8 .1M127.8 88.8h5.8M127.8 88.7h5.7M127.8 88.6h5.7"/>
<path d="M127.8 88.5h5.7M127.8 88.5h5.6M127.8 88.4h5.6M127.8 88.3h5.6M127.8 88.2h5.6M127.8 88h5.6M127.8 87.9h5.6M127.8 87.8h5.6M127.8 87.7h5.6M127.8 87.5h5.7M127.8 87.4h5.8M127.8 87.2l.5 .1"/>
<path d="M127.8 87.2h.3M127.8 87.1h.1M127.9 98.9h-4.1M127.9 96.5h2.7M127.9 92.8h2.7M127.9 96.4h2.7M128 98.8l-4.2 .1M128 96.4h2.5M128 92.9h2.5M128 96.3h2.5M128.1 96.3h2.3M128.1 93h2.3"/>
<path d="M128.1 96.2l-.4 .5M128.1 93l.3 .6M128.1 98.8h-4.3M128.1 96.2h2.3M128.1 93.1h2.2M128.1 96.2h2.2M128.2 96.1h2.1M128.2 93.1h2.1M128.2 93.2h2.1M128.2 96h2.1M128.2 93.3h2.1M128.2 98.7l-4.4 .1"/>
<path d="M128.2 95.9h2.1M128.2 95.9h2M128.2 93.3h2M128.3 95.8h1.9M128.3 93.4h1.9M128.3 95.7h1.9M128.3 93.5h1.9M128.4 98.7l-.7 .3M128.4 95.7h1.8M128.4 95.6l-.3 .6M128.4 93.6v2M128.4 93.9h1.7"/>
<path d="M128.4 94.3h1.7M128.4 94.6h1.7M128.4 95.6h1.7M128.4 95.5h1.7M128.4 95.4h1.7M128.4 95.3h1.7M128.4 95.2h1.7M128.4 95.1h1.7M128.4 95h1.7M128.4 94.9h1.7M128.4 94.8h1.7M128.4 94.7h1.7"/>
<path d="M128.4 94.5h1.7M128.4 94.4h1.7M128.4 94.2h1.7M128.4 94.1h1.7M128.4 94h1.7M128.4 93.8h1.7M128.4 93.7h1.7M128.4 93.6h1.7M130.1 93.6v2M130.1 95.6l.3 .6M130.1 93.6h-1.7M130.2 93.5h-1.9"/>
<path d="M130.2 93.4h-1.9M130.4 93l-.3 .6M130.4 96.2l.4 .5M130.6 98.7l.6 .2M130.7 92.7h-2.9M130.7 87.3h1.8M130.7 98.7h12M130.7 92.6l-2.9 .1M130.8 92.6h-3M130.8 96.7l.7 .2M130.8 98.8h11.7M130.8 87.2h1.6"/>
<path d="M130.9 92.5l-3.1 .1M131 87.2h1.2M131 98.8h11.4M131 92.5h-3.2M131.1 98.9h11.2M131.1 92.4l-3.3 .1M131.1 87.1h1M131.3 92.4h-3.5M131.4 92.3l-3.6 .1M131.5 92.3l-.7 .2-.4 .5M132 87.1l.6 .2M132 87.1h-.8l-.6 .2"/>
<path d="M132.1 92.3l.6 .2M132.2 92.3h2.4M132.2 96.9h6.8M132.3 92.4h2.3M132.3 96.9h6.6M132.5 96.8h6.2M132.5 92.4h2.1M132.6 92.5h2M132.6 96.8h6M132.7 92.5l.5 .5M132.7 96.7l-.6 .2M132.7 96.7h5.8"/>
<path d="M132.7 92.5h1.9M132.8 96.6h5.6M132.8 92.6h1.8M132.8 96.6h5.5M132.8 92.6h1.7M132.9 96.5h5.4M132.9 92.7h1.6M132.9 96.5h5.3M132.9 92.8h1.5M133 96.4h5.2M133 92.8h1.4M133.1 96.4h5"/>
<path d="M133.1 92.9h1.2M133.1 96.3h5M133.2 96.3h4.8M133.2 93h1M133.2 93v.1M133.2 96.2l-.5 .5M133.2 96.2h4.8M133.2 93.1h.9M133.2 96.1v.1M133.4 87.7v.7M133.4 88.4l.3 .7 .9 .7M133.5 87.7h-5.7"/>
<path d="M133.5 87.6h-5.7M133.5 87.5l-5.7 .1M133.5 87.4l-5.7 .1M133.6 87.3l-5.8 .1M134.2 93h-1M134.6 89.8v2.7M134.6 92.5l-.6 .6M134.6 92.3h-6.8M135 96.1h2.9M135.2 96.1h2.7M135.3 96h2.6M135.4 95.9h2.5"/>
<path d="M135.5 95.9h2.4M135.6 95.9l-.6 .2M135.6 95.8h2.2M135.7 95.8h2.1M135.7 95.7h2.1M135.8 95.7h2M135.8 95.6h2M135.8 95.6h1.9M135.9 95.5h1.8M136 95.5h1.7M136 95.4h1.7M136.1 95.4h1.6"/>
<path d="M136.1 95.3h1.6M136.2 95.3h1.5M136.2 95.2h1.5M136.3 95.1h1.4M136.4 95.1h1.3M136.5 95h1.2M136.5 94.9h1.2M136.6 94.8h1.1M136.7 94.8h1M136.7 94.7h1M136.8 94.7h.9M136.8 94.6h.9"/>
<path d="M136.9 94.6h.8M136.9 94.5h.8M137 94.4h.7M137.1 94.4h.6M137.1 94.3h.6M137.2 94.3h.5M137.2 94.2h.5M137.3 94.1h.4M137.4 94.1h.3M137.4 94h.3M137.5 93.9h.2M137.5 93.8h.2"/>
<path d="M137.6 93.7h.1M137.6 93.7l-.2 .3-1.8 1.9M137.6 93.7l.1 .1M137.7 93.8v1.8l.3 .6M138 96.2l.5 .5M138.5 96.7l.6 .2M139.8 96.9h1.7M140 96.9h1.4M140.1 96.8h1.2M140.2 96.8h.9M140.4 96.7l-.7 .2M140.4 96.7l.3-.3 .3 .3"/>
<path d="M140.4 96.7h.6M140.4 96.6h.5M140.5 96.6h.4M140.5 96.5h.3M140.6 96.5h.2M140.6 96.4h.1M141 96.7l.6 .2M142.1 85.5l4.9 .1v.9M142.1 88.1h4.9M142.1 89h6.2M142.1 83.7v7.5M142.1 87h6.2"/>
<path d="M142.1 91.2l1.1 1.2M142.1 83.7l.6 .8M142.1 86.4l6.2 .1M142.1 91.2h3.9M142.1 91.1h3.9M142.1 91h3.9M142.1 90.9h3.9M142.1 90.3h6.2M142.1 90.2h6.2M142.1 90.1h6.2M142.1 90h6.2M142.1 89.9h6.2"/>
<path d="M142.1 89.8h6.2M142.1 89.7h6.2M142.1 89.6h6.2M142.1 89.5h6.2M142.1 89.4h6.2M142.1 89.3h6.2M142.1 89.2h6.2M142.1 89.1h6.2M142.1 88.9l1.4 .1M142.1 88.9h1.2M142.1 88.8l1.2 .1M142.1 88.8h1.1"/>
<path d="M142.1 88.7l1 .1M142.1 88.7h1M142.1 88.6h.9M142.1 88.5h.9M142.1 88.5h.8M142.1 88.4h.8M142.1 88.3h.8M142.1 88.2h.8M142.1 88.1h.7M142.1 88h.7M142.1 87.9h.8M142.1 87.5h.9"/>
<path d="M142.1 87.1h6.2M142.1 86.9h6.2M142.1 86.8h6.2M142.1 86.7h6.2M142.1 86.6h6.2M142.1 86.5h6.2M142.1 86.4h1.4M142.1 86.3l1.2 .1M142.1 86.3h1.2M142.1 86.2l1.1 .1M142.1 86.2h1M142.1 86.1h1"/>
<path d="M142.1 86.1h.9M142.1 86h.9M142.1 85.9h.8M142.1 85.8h.8M142.1 85.7h.8M142.1 85.6h.7M142.1 85.5h.7M142.1 85.4h.7M142.1 85.4h.8M142.1 85.3h.8M142.1 85.1h.8M142.1 84.7h1.2"/>
<path d="M142.1 84.6l1.1 .1M142.1 84.6h.9M142.1 84.5l.8 .1M142.1 84.5h.6M142.1 84.4l.6 .1M142.1 84.4h.5M142.1 84.3h.5M142.1 84.2h.4M142.1 84.2h.3M142.1 84.1h.3M142.1 84.1h.2M142.1 84h.2"/>
<path d="M142.1 83.9h.1M142.1 83.8h.1M142.1 83.7h.1M142.2 91.3h3.8M142.2 91.4h3.8M142.3 91.4h3.7M142.3 91.5h3.7M142.4 91.5h3.6M142.4 96.9h2.8M142.4 91.6h3.6M142.5 96.9h2.7M142.5 91.6l3.5 .1"/>
<path d="M142.5 91.7h3.6M142.6 91.7l3.5 .1M142.6 91.8h3.6M142.6 96.8h2.6M142.7 91.8l3.5 .1M142.7 91.9h3.6M142.7 84.5l.6 .2M142.8 98.7l-.6 .2M142.8 96.8h2.4M142.8 91.9l3.5 .1M142.8 85.4v.2M142.8 88v.2"/>
<path d="M142.8 88.2l.1 .1M142.8 85.6l.1 .2M142.8 92h3.6M142.9 87.8l-.1 .2M142.9 88.3v.2M142.9 85.3l-.1 .1M142.9 85.8v.2M142.9 87.8h-.8M142.9 85.3h-.8M142.9 96.7l-.6 .2M142.9 96.7h2.3M142.9 92.1h3.6"/>
<path d="M142.9 85.2h-.8M142.9 87.7h-.8M142.9 87.7v.1M142.9 88.5l.1 .2M142.9 85.1v.2M142.9 86l.1 .1M142.9 96.6h2.3M143 87.6h-.9M143 85l-.9 .1M143 92.2h5.3M143 96.6h2.2M143 87.5l-.9 .1"/>
<path d="M143 85h-.9M143 88.7l.2 .1M143 84.9l-.1 .2M143 86.1l.2 .2M143 96.5h2.2M143 84.9l-.9 .1M143.1 92.3h5.2M143.1 96.5h2.1M143.1 87.4l-1 .1M143.1 84.9h-1M143.1 87.4h-1M143.2 96.4h2"/>
<path d="M143.2 88.8l.1 .1M143.2 86.3l.1 .1M143.2 92.3h5.1M143.2 84.8l-1.1 .1M143.2 92.4h5.1M143.2 87.3l-1.1 .1M143.2 84.8h-1.1M143.2 92.4l.3 .9M143.3 96.3h1.9M143.3 92.4h5M143.3 87.3h-1.2M143.3 92.5h5"/>
<path d="M143.3 84.7l-.3 .2M143.3 84.7l-1.2 .1M143.3 88.9l.2 .1M143.3 86.4h.2M143.3 92.6h5M143.4 96.2l-.5 .5M143.4 96.2h1.8M143.4 92.7h4.9M143.4 92.8h4.9M143.4 96.1h1.8M143.4 87.2l-1.3 .1M143.4 92.9h4.9"/>
<path d="M143.4 96h1.8M143.5 93.1h4.8M143.5 93.3l.1 .3M143.5 93.3h4.8M143.5 93.2h4.8M143.5 93h4.8M143.5 89h.2M143.5 86.4l.2 .1M143.5 95.9h1.7M143.5 95.8h1.7M143.5 93.4h4.8M143.6 95.8h1.6"/>
<path d="M143.6 87.2h-1.5M143.6 95.7h1.6M143.6 93.5h4.7M143.6 95.6l-.2 .6M143.6 93.6v2M143.6 95.6h1.6M143.6 95.5h1.6M143.6 95.4h1.6M143.6 95.3h1.6M143.6 95.2h1.6M143.6 95.1h1.7M143.6 95h1.7"/>
<path d="M143.6 94.9h1.8M143.6 94.8h1.8M143.6 94.4h2.1M143.6 93.9h4.7M143.6 93.8h4.7M143.6 93.7h4.7M143.6 93.6h4.7M143.7 87.1l-.4 .1-.4 .5M143.7 85.5v1M143.7 87.1v1.9M143.7 87.3h.1M143.7 88.9h.1"/>
<path d="M143.7 88.8h.1M143.7 88.7h.1M143.7 88.6h.1M143.7 88.5h.1M143.7 88.4h.1M143.7 88.3h.1M143.7 88.2h.1M143.7 88.1h.1M143.7 88h.1M143.7 87.9h.1M143.7 87.8h.1M143.7 87.7h.1"/>
<path d="M143.7 87.6h.1M143.7 87.5h.1M143.7 87.4h.1M143.7 87.2h.1M143.7 86.4h.1M143.7 86.3h.1M143.7 86.2h.1M143.7 86.1h.1M143.7 86h.1M143.7 85.9h.1M143.7 85.8h.1M143.7 85.7h.1"/>
<path d="M143.7 85.6h.1M143.8 85.5v1M143.8 87.1v1.9M143.8 87.1l.6 .3M144 87.2h2.1M144 89h-.2M144 86.4l-.2 .1M144 89h2M144 86.4h2M144.1 87.2h1.8M144.2 88.9h1.6M144.2 86.4h1.6"/>
<path d="M144.3 87.3h1.5M144.3 88.9h1.5M144.3 86.3h1.5M144.3 87.3h1.4M144.3 84.8h1.4M144.4 87.4l.2 .3M144.4 88.8l-.4 .2M144.4 86.3l-.4 .1M144.4 84.8l.1 .1M144.4 88.8h1.3M144.4 86.3h1.3M144.4 84.8h1.3"/>
<path d="M144.4 87.4h1.2M144.4 88.8h1.2M144.4 86.2h1.2M144.4 84.9h1.2M144.5 88.7h1.1M144.5 86.1h1.1M144.5 84.9l.1 .2M144.5 87.5h1.1M144.5 84.9h1.1M144.5 88.6h1M144.5 86.1h1M144.5 87.5h1"/>
<path d="M144.5 85h1M144.5 86h1M144.6 88.5h.9M144.6 87.6h.9M144.6 86h.9M144.6 87.7l.1 .1M144.6 85.1l.1 .2M144.6 88.5h.8M144.6 85.9h.8M144.6 88.4h.8M144.6 87.7h.8M144.7 88.3l-.3 .5"/>
<path d="M144.7 87.8v.2M144.7 85.3v.1M144.7 85.8l-.3 .5M144.7 88.3h.7M144.7 87.8h.7M144.7 85.8h.7M144.7 88.2h.7M144.7 87.9h.7M144.7 85.7h.7M144.7 85.3h.7M144.7 88v.3M144.7 85.4v.4"/>
<path d="M144.7 88.1h.7M144.7 88h.7M144.7 85.6h.7M144.7 85.5h.7M144.7 85.4h.7M144.8 98.7l.6 .2M144.9 98.7h1.5M145.1 98.8h.7M145.2 95.4v1.9M145.2 97.3l.2 .7 .5 .5 .6 .2M145.2 95.2l-1.6 .1M145.2 98.9h.5"/>
<path d="M145.3 84.7h.6M145.4 85.4v.2M145.4 88v.3M145.4 85.6v.2M145.4 94.9h-1.8M145.4 87.9h-.7M145.4 85.4h-.7M145.4 85.3v.1M145.4 88.3l.3 .5M145.4 85.8l.3 .5M145.4 87.8v.2M145.4 94.8h-1.8"/>
<path d="M145.4 85.3h-.7M145.4 87.8h-.8M145.4 85.2h-.8M145.4 94.7l-.2 .7M145.4 94.7h-1.8M145.5 85.1l-.1 .2M145.5 87.7l-.1 .1M145.5 87.7h-.9M145.5 85.1h-.9M145.5 84.6h.3M145.5 94.7h-1.9M145.5 94.6h-1.9"/>
<path d="M145.6 84.9l-.1 .2M145.6 94.6h-2M145.6 84.6h.1M145.6 84.5l-.5 .3M145.6 84.5l.3 .2M145.6 94.5h-2M145.7 84.8l-.1 .1M145.7 86.3l.1 .1M145.7 87.4l-.2 .3M145.7 88.8l.1 .1M145.8 94.4h-2.2M145.8 94.3l-2.2 .1"/>
<path d="M145.8 84.7l-1.4 .1M145.8 84.7l-.1 .1M145.8 86.4h.2M145.8 88.9l.2 .1M145.9 94.3h-2.3M145.9 94.2l-2.3 .1M145.9 84.7h-.7M145.9 84.7h.1M145.9 84.7h-.1M145.9 98.8l-.3 .1M146 90.9v.7M146 91.6l.6 .6"/>
<path d="M146 86.4l.2 .1M146 89h.2M146 94.2h-2.4M146 90.8l-3.9 .1M146.1 94.1h-2.5M146.1 90.8h-4M146.2 90.7l-4.1 .1M146.2 87.1l-.5 .3M146.2 90.7h-4.1M146.3 94.1h-2.7M146.3 90.6l-4.2 .1M146.3 90.6h-4.2"/>
<path d="M146.3 94h-2.7M146.4 90.5l-4.3 .1M146.4 90.5h-4.3M146.5 98.7h-22.7M146.5 98.7l-1.5 .1M146.5 90.4h-4.4M146.5 94h-2.9M146.6 90.3l-.6 .6M146.6 93.9l-.7 .3-.5 .5M146.9 85.5v1M146.9 87.1v1.9M146.9 90.3v1.9"/>
<path d="M146.9 87.3h.1M146.9 92.1h.1M146.9 92h.1M146.9 91.9h.1M146.9 91.8h.1M146.9 91.7h.1M146.9 91.6h.1M146.9 91.5h.1M146.9 91.4h.1M146.9 91.3h.1M146.9 91.2h.1M146.9 91.1h.1"/>
<path d="M146.9 91h.1M146.9 90.9h.1M146.9 90.8h.1M146.9 90.7h.1M146.9 90.6h.1M146.9 90.5h.1M146.9 90.4h.1M146.9 88.9h.1M146.9 88.8h.1M146.9 88.7h.1M146.9 88.6h.1M146.9 88.5h.1"/>
<path d="M146.9 88.4h.1M146.9 88.3h.1M146.9 88.2h.1M146.9 88.1h.1M146.9 88h.1M146.9 87.9h.1M146.9 87.8h.1M146.9 87.7h.1M146.9 87.6h.1M146.9 87.5h.1M146.9 87.4h.1M146.9 87.2h.1"/>
<path d="M146.9 86.4h.1M146.9 86.3h.1M146.9 86.2h.1M146.9 86.1h.1M146.9 86h.1M146.9 85.9h.1M146.9 85.8h.1M146.9 85.7h.1M146.9 85.6h.1M147 87.1v1.9M147 90.3v1.9M147.3 93.9l1 .6"/>
<path d="M147.3 90.3l.6 .6v.7l-.6 .6M147.3 90.4h1M147.4 92.1h.9M147.4 94h.9M147.4 90.4h.9M147.5 92h.8M147.5 90.5h.8M147.5 94h.8M147.6 90.6h.7M147.6 91.9h.7M147.6 94.1h.7M147.7 90.7h.6"/>
<path d="M147.7 87.1l.6 .4M147.7 91.8h.6M147.8 94.1h.5M147.8 91.7h.5M147.8 90.8h.5M147.8 87.2h.5M147.9 86.4l-.2 .1M147.9 89h-.2M147.9 94.2h.4M147.9 91.6h.4M147.9 91.5h.4M147.9 91.4h.4"/>
<path d="M147.9 91.3h.4M147.9 91.2h.4M147.9 91.1h.4M147.9 91h.4M147.9 90.9h.4M147.9 89h.4M147.9 86.4h.4M148 87.2h.3M148 94.2h.3M148 94.3h.3M148 88.9h.3M148 86.4h-.1"/>
<path d="M148 88.9l-.1 .1M148 86.4h.3M148.1 87.3h.2M148.1 94.3h.2M148.1 88.9h.2M148.1 86.3h.2M148.1 94.4h.2M148.2 86.3l-.2 .1M148.2 88.8l-.2 .1M148.2 94.4h.1M148.2 88.8h.1M148.2 86.3h.1"/>
<path d="M148.2 94.5h.1M148.2 87.4h.1M148.2 86.2h.1M148.3 87.4h.1M148.3 91.2l-6.2 .1M148.3 90.3h-6.2M148.3 87.1l-6.2 .1M148.3 88.7l-.1 .1M148.3 86.2l-.1 .1M148.3 86.2v1.2M148.3 88.7v5.8M148.3 93.9h-4.7"/>
<path d="M148.3 94.5h.1M148.3 86.2h.1M151.3 96.9l16.4 .1M151.3 96.1h15.6M151.3 98.9h2M151.3 98.7h22.8M151.3 98.9h.1M151.3 94.4v4.5M151.3 94.6h15.5M151.3 97.1l22.8 .1M151.3 98.6h22.8M151.3 98.5h22.8"/>
<path d="M151.3 98.4h22.8M151.3 98.3h22.8M151.3 98.2h22.8M151.3 98.1h22.8M151.3 98h22.8M151.3 97.9h22.8M151.3 97.8h22.8M151.3 97.7h22.8M151.3 97.6h22.8M151.3 97.5h22.8M151.3 97.4h22.8M151.3 97.3h22.8"/>
<path d="M151.3 97.2h22.8M151.3 97.1h16.8M151.3 97l16.7 .1M151.3 97h16.5M151.3 96.9h16.3M151.3 96.8l16.2 .1M151.3 96.8h16.1M151.3 96.7l16.1 .1M151.3 96.7h16M151.3 96.6h16M151.3 96.6h15.9M151.3 96.5h15.9"/>
<path d="M151.3 96.5h15.8M151.3 96.4h15.8M151.3 96.4h15.7M151.3 96.3h15.7M151.3 96.2h15.7M151.3 96h15.6M151.3 95.9h15.5M151.3 95.8h15.5M151.3 95.7h15.5M151.3 95.6h15.5M151.3 95.5h15.5M151.3 95.4h15.5"/>
<path d="M151.3 95.3h15.5M151.3 95.2h15.5M151.3 95.1h15.5M151.3 95h15.5M151.3 94.9h15.5M151.3 94.8h15.5M151.3 94.7h15.5M151.3 94.6h9.2M151.3 94.5h9M151.3 94.4l8.9 .1M151.3 94.4h8.8M153.4 98.8l-2.1 .1"/>
<path d="M153.6 98.8l-.4 .1M155.6 98.8l.6 .2 .4 .5M155.7 98.8h18.4M155.8 98.9h18.3M155.9 99h18.2M156 99h18.1M156.2 99.1h17.9M156.3 99.2h17.8M156.4 99.3h17.7M156.5 99.4h17.6M156.6 99.5h17.5M156.6 99.5l.3 .6"/>
<path d="M156.7 99.6h17.4M156.7 99.7h17.4M156.8 99.8h17.3M156.8 99.9h17.3M159.9 94.4l.6 .2M160 94.4h-8.7M162.3 94.6h4.5M162.4 94.5h4.4M162.6 94.5h4.2M162.7 94.4h4.1M162.8 94.4h4M162.9 94.3l-.7 .3"/>
<path d="M162.9 94.3h3.9M163 94.2h3.8M163.1 94.1h3.7M163.2 94h3.6M163.4 93.8h3.5M163.4 93.7h3.5M163.4 93.6h3.5M163.5 92.2h3.5M163.5 93.5h3.5M163.5 92.3h3.5M163.5 93.4h3.5M163.6 93.4h3.4"/>
<path d="M163.6 92.3h3.4M163.6 92.4h3.4M163.6 93.3h3.4M163.6 92.5h3.4M163.6 92.5v.7M163.6 93.1h3.4M163.6 93.2l-.2 .7-.5 .4M163.6 93.2h3.4M163.6 93h3.4M163.6 92.9h3.4M163.6 92.8h3.4M163.6 92.7h3.4"/>
<path d="M163.6 92.6h3.4M166.8 94.1v1.6M166.8 95.7l.2 .7 .5 .5 .7 .3M166.8 94h-3.6M166.8 93.9h-3.5M166.9 93.8h-3.5M166.9 93.7h-3.5M167 93.5l-3.5 .1M167 92.2l-3.5-.1 .1 .4M167 92.2v1.3M167 93.5l-.2 .6M169 97.1h5.1"/>
<path d="M169.1 97.1h5M169.2 97h4.9M169.3 97h4.8M169.5 96.9h4.6M169.6 96.8h4.5M169.7 96.8h4.4M169.7 96.7h4.4M169.8 96.6h4.3M169.9 96.5h4.2M170 96.4h4.1M170.1 93.5l.2 .6M170.1 93.1h4"/>
<path d="M170.1 96.3h4M170.1 93.5h4M170.1 93.4h4M170.1 93.3h4M170.1 93.2h4M170.1 93h4M170.1 92.9h4M170.1 92.8h4M170.1 92.7h4M170.1 92.6h4M170.1 92.5h4M170.1 92.4h4"/>
<path d="M170.1 96.2h4M170.1 93.6h4M170.1 96.1h4M170.1 93.7h4M170.2 96.1h3.9M170.2 93.7h3.9M170.2 96h3.9M170.2 93.8h3.9M170.2 95.9h3.9M170.2 93.9h3.9M170.2 95.8h3.9M170.2 94h3.9"/>
<path d="M170.3 95.8h3.8M170.3 94.1h3.8M170.3 94h3.8M170.3 94.1v1.6M170.3 94.3h3.8M170.3 94.6h3.8M170.3 95.7l-.3 .7-.5 .5-.6 .3M170.3 95.7h3.8M170.3 95.6h3.8M170.3 95.5h3.8M170.3 95.4h3.8M170.3 95.3h3.8"/>
<path d="M170.3 95.2h3.8M170.3 95.1h3.8M170.3 95h3.8M170.3 94.9h3.8M170.3 94.8h3.8M170.3 94.7h3.8M170.3 94.5h3.8M170.3 94.4h3.8M170.3 94.2h3.8M171.9 92.4h2.2M172.1 92.3h2M172.2 92.2h1.9"/>
<path d="M172.4 92.2h1.7M172.5 92.1h1.6M172.6 92.1h1.5M172.6 92h1.5M172.7 92h1.4M172.7 91.9h1.4M172.7 89.3l.3 .3M172.7 86.8l.3 .3M172.7 84.3l.3 .2M172.7 81.7l.3 .3M172.7 89.3h1.4M172.7 86.8h1.4"/>
<path d="M172.7 84.3h1.4M172.7 81.7h1.4M172.8 91.9h1.3M172.8 89.3h1.3M172.8 86.8h1.3M172.8 84.3h1.3M172.8 84.2h1.3M172.8 81.8h1.3M172.8 81.7h1.3M172.8 91.8h1.3M172.8 89.4h1.3M172.8 86.9h1.3"/>
<path d="M172.8 86.7h1.3M172.8 89.5h1.3M172.8 84.4h1.3M172.8 81.6h1.3M172.9 91.8h1.2M172.9 89.2h1.2M172.9 86.7h1.2M172.9 84.1h1.2M172.9 81.6h1.2M172.9 84.4h1.2M172.9 81.9h1.2M172.9 91.7h1.2"/>
<path d="M172.9 89.5h1.2M172.9 87h1.2M172.9 86.6h1.2M172.9 81.5h1.2M173 87h1.1M173 89.6h1.1M173 84.5h1.1M173 81.9h1.1M173 91.7h1.1M173 89.1h1.1M173 86.6h1.1M173 84h1.1"/>
<path d="M173 81.5h1.1M173 82h1.1M173 87.1l.3 .6M173 89.6l.3 .7M173 84.5l.3 .7M173 82l.3 .7M173 91.6h1.1M173 89h1.1M173 87.1h1.1M173 86.5h1.1M173 81.4h1.1M173 91.5h1.1"/>
<path d="M173 89.7h1.1M173 84.6h1.1M173 83.9h1.1M173.1 91.5h1M173.1 89.7h1M173.1 89h1M173.1 87.2h1M173.1 86.4h1M173.1 84.6h1M173.1 82.1h1M173.1 91.4h1M173.1 89.8h1"/>
<path d="M173.1 88.9h1M173.1 84.7h1M173.1 83.8h1M173.1 81.3h1M173.1 87.3h1M173.1 86.3h1M173.1 82.2h1M173.1 91.3h1M173.1 89.9h1M173.1 88.8h1M173.1 84.8h1M173.1 83.7h1"/>
<path d="M173.1 82.3h1M173.1 81.2h1M173.1 87.4h1M173.1 86.2h1M173.2 90h.9M173.2 87.4h.9M173.2 84.9h.9M173.2 83.6h.9M173.2 82.4h.9M173.2 81.1h.9M173.2 91.2h.9M173.2 88.7h.9"/>
<path d="M173.2 88.6h.9M173.2 87.5h.9M173.2 86.1h.9M173.2 81h.9M173.2 90.1h.9M173.2 85h.9M173.2 83.5h.9M173.2 82.5h.9M173.2 91.1h.9M173.2 88.5h.9M173.2 87.6h.9M173.2 86h.9"/>
<path d="M173.2 80.9h.9M173.2 90.2h.9M173.2 87.7h.9M173.2 85.1h.9M173.2 83.4h.9M173.2 82.6h.9M173.3 91h.8M173.3 90.3h.8M173.3 88.5h.8M173.3 87.7h.8M173.3 85.9h.8M173.3 85.2h.8"/>
<path d="M173.3 83.4h.8M173.3 82.6h.8M173.3 80.8h.8M173.3 80.1h.8M173.3 88.1h.8M173.3 91l-.3 .6-.5 .5-.6 .3M173.3 80.1v.7M173.3 82.7v.7M173.3 85.2v.7M173.3 87.7v.7M173.3 90.3v.7M173.3 88.4l-.6 .9"/>
<path d="M173.3 85.9l-.6 .9M173.3 83.4l-.6 .9M173.3 80.8l-.6 .9M173.3 85.5h.8M173.3 90.9h.8M173.3 90.8h.8M173.3 90.7h.8M173.3 90.6h.8M173.3 90.5h.8M173.3 90.4h.8M173.3 88.4h.8M173.3 88.3h.8"/>
<path d="M173.3 88.2h.8M173.3 88h.8M173.3 87.9h.8M173.3 87.8h.8M173.3 85.8h.8M173.3 85.7h.8M173.3 85.6h.8M173.3 85.4h.8M173.3 85.3h.8M173.3 83.3h.8M173.3 83.2h.8M173.3 83.1h.8"/>
<path d="M173.3 83h.8M173.3 82.9h.8M173.3 82.8h.8M173.3 82.7h.8M173.3 80.7h.8M173.3 80.6h.8M173.3 80.5h.8M173.3 80.4h.8M173.3 80.3h.8M173.3 80.2h.8M174.1 92.4h-4v1.1M174.1 98.8h-22.8"/>
<path d="M123.8 105.5l23.2 .1v.9M123.8 118.2h28.4M123.8 119.1l28.7 .1M123.8 116.6h4.5M123.8 115.6h28.4M123.8 114.7l4.2 .1M123.8 106.5h4.6M123.8 104.6h4.3M123.8 106.6h24.5M123.8 104.5h4M123.8 108.8h22M123.8 116.7h28.8"/>
<path d="M123.8 114.7h4.1M123.8 119.9h50.3M123.8 119.7l29.4 .1M123.8 113.9h3.3M123.8 114.2h3.5M123.8 111.3h3.3M123.8 111.6l3.5 .1M123.8 109.6h3.4M123.8 103.1h3.1M123.8 106.5l4.8 .1M123.8 103.8h3.3M123.8 104h3.4"/>
<path d="M123.8 101.2h3.3M123.8 120h50.3M123.8 119.8l29.7 .1M123.8 119.8h29.5M123.8 119.7h29.3M123.8 119.6l29.2 .1M123.8 119.6h29.1M123.8 119.5h29M123.8 119.4h28.9M123.8 119.3h28.8M123.8 119.2h28.7M123.8 119.1h22.2"/>
<path d="M123.8 119l22.1 .1M123.8 119h22M123.8 118.9l21.9 .1M123.8 118.9h21.8M123.8 118.8l21.8 .1M123.8 118.8h21.7M123.8 118.7h21.7M123.8 118.6h21.6M123.8 118.5h21.6M123.8 118.4l21.6 .1M123.8 118.4h21.6M123.8 118.3l21.6 .1"/>
<path d="M123.8 118.3h21.6M123.8 118.1h21.6M123.8 118h21.6M123.8 117.9h21.6M123.8 117.8h21.7M123.8 117.2h28.8M123.8 116.9h29M123.8 116.9h28.9M123.8 116.8h28.9M123.8 116.8h28.8M123.8 116.6l4.6 .1M123.8 116.5l4.4 .1"/>
<path d="M123.8 116.5h4.3M123.8 116.4l4.2 .1M123.8 116.4h4.2M123.8 116.3l4.1 .1M123.8 116.3h4.1M123.8 116.2h4M123.8 116.1h4M123.8 116h3.9M123.8 115.9h3.9M123.8 115.8h3.9M123.8 115.7h3.9M123.8 115.6h3.9"/>
<path d="M123.8 115.5h3.9M123.8 115.4h3.9M123.8 115.1h4.1M123.8 114.8h4.3M123.8 114.6l3.9 .1M123.8 114.6h3.9M123.8 114.5l3.8 .1M123.8 114.5h3.8M123.8 114.4h3.7M123.8 114.3h3.6M123.8 114.1h3.4M123.8 114l3.4 .1"/>
<path d="M123.8 114h3.3M123.8 113.9l3.3 .1M123.8 113.8l3.3 .1M123.8 113.8h3.3M123.8 113.7h3.2M123.8 113.6h3.2M123.8 113.5h3.2M123.8 113.5h3.1M123.8 113.4h3.1M123.8 113.3h3.1M123.8 113.2h3.1M123.8 113.1h3.1"/>
<path d="M123.8 113h3.1M123.8 112.9h3.1M123.8 112.8h3.1M123.8 112.7h3.2M123.8 111.8l3.7 .1M123.8 111.8h3.6M123.8 111.7l3.6 .1M123.8 111.7h3.5M123.8 111.6h3.4M123.8 111.5h3.4M123.8 111.5h3.3M123.8 111.4h3.3"/>
<path d="M123.8 111.2l3.3 .1M123.8 111.2h3.2M123.8 111.1h3.2M123.8 111h3.2M123.8 110.9h3.1M123.8 110.8h3.1M123.8 110.7h3.1M123.8 110.6h3.1M123.8 110.5h3.1M123.8 110.4h3.1M123.8 110.3h3.1M123.8 109.8h3.3"/>
<path d="M123.8 109.7h3.4M123.8 109.5h3.5M123.8 109.2h3.9M123.8 108.8h21.9M123.8 108.7h21.8M123.8 108.6l21.8 .1M123.8 108.6h21.7M123.8 108.5h21.7M123.8 108.4l21.6 .1M123.8 108.4h21.6M123.8 108.3h21.6M123.8 108.2h21.6"/>
<path d="M123.8 108.1h21.6M123.8 108h21.6M123.8 107.9h21.6M123.8 107.8h21.6M123.8 107.6h21.7M123.8 107.1h24.5M123.8 107h24.5M123.8 106.9h24.5M123.8 106.8h24.5M123.8 106.7h24.5M123.8 106.4h4.4M123.8 106.3h4.3"/>
<path d="M123.8 106.3h4.2M123.8 106.2h4.2M123.8 106.2h4.1M123.8 106.1h4.1M123.8 106l4 .1M123.8 106h4M123.8 105.9h4M123.8 105.8l3.9 .1M123.8 105.8h3.9M123.8 105.7h3.9M123.8 105.6h3.9M123.8 105.5h3.9"/>
<path d="M123.8 105.4h3.9M123.8 105.3h3.9M123.8 105.1h4M123.8 104.9h4.1M123.8 104.7h4.3M123.8 104.6h4.1M123.8 104.5h3.9M123.8 104.4h3.8M123.8 104.3h3.8M123.8 104.2l3.7 .1M123.8 104.2h3.6M123.8 104.1l3.6 .1"/>
<path d="M123.8 104.1h3.5M123.8 104h3.5M123.8 103.9h3.4M123.8 103.7h3.3M123.8 103.6h3.3M123.8 103.5l3.2 .1M123.8 103.5h3.2M123.8 103.4l3.2 .1M123.8 103.4h3.2M123.8 103.3l3.2 .1M123.8 103.3h3.1M123.8 103.2h3.1"/>
<path d="M123.8 103h3.1M123.8 102.9h3.1M123.8 102.8h3.1M123.8 102.7h3.1M123.8 102.4h3.2M123.8 102.3h3.3M123.8 102.2h3.3M123.8 102.1h3.3M123.8 102.1h3.4M123.8 102h3.4M123.8 101.8h3.6M123.8 101.7h3.7"/>
<path d="M123.8 101.6l3.6 .1M123.8 101.6h3.6M123.8 101.5l3.5 .1M123.8 101.5h3.5M123.8 101.4l3.4 .1M123.8 101.4h3.4M123.8 101.3h3.4M123.8 101.3h3.3M123.8 101.1h3.3M123.8 101h3.2M123.8 100.9h3.2M123.8 100.8h3.2"/>
<path d="M123.8 100.8h3.1M123.8 100.7h3.1M123.8 100.6h3.1M123.8 100.5h3.1M123.8 100.4h3.1M123.8 100.3h3.1M123.8 100.2h3.1M123.8 100.1h3.1M123.8 100h3.2M126.9 100.1v.7M126.9 102.6v.8M126.9 110.3v.7"/>
<path d="M126.9 112.8v.7M126.9 100.8l.3 .7M126.9 103.4l.3 .6M126.9 111l.6 .9M126.9 113.5l.3 .7 .5 .5M127 112.8h-3.2M127 110.2l-3.2 .1M127 102.6h-3.2M127 100.1h-3.2M127 110.2h-3.2M127 112.7h-3.2M127 110.1l-3.2 .1"/>
<path d="M127 102.5h-3.2M127 112.6h-3.2M127 110.1h-3.2M127 110h-3.2M127 102.4h-3.2M127.1 112.5h-3.3M127.1 110h-3.3M127.1 109.9h-3.3M127.1 102.3h-3.3M127.1 112.4h-3.3M127.1 112.3h-3.3M127.1 109.7l-3.3 .1"/>
<path d="M127.2 112.2l-3.4 .1M127.2 112.2h-3.4M127.2 109.6l-3.4 .1M127.2 101.5l.3 .2M127.2 104l.9 .7M127.2 109.6l-.3 .7M127.2 112.1l-.3 .7M127.2 112.1l-3.4 .1M127.3 102h-3.5M127.3 112.1h-3.5M127.3 109.5l-3.5 .1M127.3 101.9h-3.5"/>
<path d="M127.3 112l-3.5 .1M127.4 112h-3.6M127.4 101.9h-3.6M127.4 109.4l-3.6 .1M127.4 111.9l-3.6 .1M127.4 109.4h-3.6M127.5 111.9h-3.7M127.5 101.7l-3.7 .1M127.5 101.7l-.6 .9M127.5 111.9l-.3 .2M127.5 109.3l-3.7 .1M127.6 109.3h-3.8"/>
<path d="M127.6 109.2h-3.8M127.7 105.4v.2M127.7 115.6v.2M127.7 105.6v.2M127.7 115.8v.2M127.7 105.4h-3.9M127.7 109.1l-.5 .5M127.7 105.2v.2M127.7 105.8l.1 .2M127.7 114.7l.4 .2M127.7 115.4v.2M127.7 116l.4 .5 .5 .2"/>
<path d="M127.7 115.5h-3.9M127.7 109.1l-3.9 .1M127.7 105.3h-3.9M127.7 115.4h-3.9M127.7 105.2h-3.9M127.8 115.3h-4M127.8 105.2h-4M127.8 105.1h-4M127.8 105.1l-.1 .1M127.8 106l.3 .3M127.8 109.1h-4M127.8 115.2l-.1 .2"/>
<path d="M127.8 115.2l-4 .1M127.8 115.2h-4M127.8 105h-4M127.9 115.1h-4.1M127.9 104.9h-4.1M127.9 104.9l-.1 .2M128 109l-4.2 .1M128 115h-4.2M128 104.8l-4.2 .1M128 104.8h-4.2M128.1 106.3l.5 .3M128.1 114.9l-.3 .3"/>
<path d="M128.1 114.9h-4.3M128.1 109h-4.3M128.1 104.7l-4.3 .1M128.1 104.7l-.2 .2M128.2 108.9h-4.4M128.3 108.9h-4.5M128.4 108.8l-.7 .3M129.5 116.6h.1M129.5 106.5h.1M129.5 105.5v1.1M129.5 115.7v1M129.5 116.5h.1"/>
<path d="M129.5 116.4h.1M129.5 116.3h.1M129.5 116.2h.1M129.5 116.1h.1M129.5 116h.1M129.5 115.9h.1M129.5 115.8h.1M129.5 115.7h.1M129.5 106.4h.1M129.5 106.3h.1M129.5 106.2h.1M129.5 106.1h.1"/>
<path d="M129.5 106h.1M129.5 105.9h.1M129.5 105.8h.1M129.5 105.7h.1M129.5 105.6h.1M130.4 106.6h17.9M130.6 106.5h17.7M130.6 116.7h21.9M130.6 108.8l.6 .3M130.6 108.9h12.1M130.7 116.6h21.8M130.7 106.4h12.7"/>
<path d="M130.7 106.4l-.4 .2M130.7 108.9h11.9M130.8 116.6h12.5M130.8 106.4h12.5M130.8 104.7h.1M130.8 114.9h.1M130.8 114.9h12.5M130.9 116.5h12.4M130.9 104.7h12.4M130.9 104.6h15M130.9 114.9h12.4M130.9 109h11.6"/>
<path d="M130.9 106.3l-.2 .1M130.9 104.7l.1 .2M130.9 116.5l-.6 .2M130.9 114.9l.2 .3M130.9 106.3h12.4M130.9 104.8h12.3M130.9 116.5h12.3M130.9 106.3h12.3M131 116.4h12.2M131 115h12.2M131 114.8h14.8M131 109h11.4"/>
<path d="M131 106.2h12.2M131 116.4h12.1M131 106.2h12.1M131 106.2l-.1 .1M131 104.9l.1 .2M131 116.4l-.1 .1M131 115.1h12.1M131 104.6h14.8M131.1 116.3h12M131.1 104.9h12M131.1 114.7h14.6M131.1 106.1h11.9"/>
<path d="M131.1 116.2h11.9M131.1 105h11.9M131.1 104.5h14.5M131.1 106l-.1 .2M131.1 105.1l.2 .3-.2 .6M131.1 109.1h11.1M131.1 116.2l-.1 .2M131.1 115.2l.2 .4M131.1 115.2h11.8M131.1 106h11.8M131.1 105.1h11.8M131.2 116.1h11.7"/>
<path d="M131.2 115.3h11.7M131.2 106h11.7M131.2 115.3h11.6M131.2 105.9h11.6M131.2 105.2h11.6M131.2 104.5l-.4 .2M131.2 114.7l-.4 .2M131.2 116h11.6M131.2 115.4h11.6M131.2 116l-.1 .2M131.2 115.9h11.6M131.2 105.8h11.6"/>
<path d="M131.2 105.3h11.6M131.3 115.8h11.5M131.3 115.5h11.5M131.3 105.7h11.5M131.3 105.4h11.5M131.3 115.6l-.1 .4M131.3 115.7h11.5M131.3 115.6h11.5M131.3 105.6h11.5M131.3 105.5h11.5M142.8 108.8l-.6 .3M142.8 115.3v.8l.6 .5"/>
<path d="M142.8 105.2v.7M142.8 105.9l.6 .6M142.9 105.1h-11.7M143 115.2h-11.9M143 115.1h-11.9M143.1 104.9h-12.1M143.2 104.8h-12.2M143.3 104.7h-12.5M143.4 114.8h-12.6M143.4 114.8l-.6 .5M143.4 104.6l-.6 .6M143.7 104.6v1.9"/>
<path d="M143.7 114.8v1.8M143.7 116.5h.1M143.7 116.4h.1M143.7 116.3h.1M143.7 116.2h.1M143.7 116.1h.1M143.7 116h.1M143.7 115.9h.1M143.7 115.8h.1M143.7 115.7h.1M143.7 115.6h.1M143.7 115.5h.1"/>
<path d="M143.7 115.4h.1M143.7 115.3h.1M143.7 115.2h.1M143.7 115.1h.1M143.7 115h.1M143.7 114.9h.1M143.7 114.8h.1M143.7 106.4h.1M143.7 106.3h.1M143.7 106.2h.1M143.7 106.1h.1M143.7 106h.1"/>
<path d="M143.7 105.9h.1M143.7 105.8h.1M143.7 105.7h.1M143.7 105.6h.1M143.7 105.5h.1M143.7 105.4h.1M143.7 105.3h.1M143.7 105.2h.1M143.7 105.1h.1M143.7 105h.1M143.7 104.9h.1M143.7 104.8h.1"/>
<path d="M143.7 104.7h.1M143.8 104.6v1.9M143.8 114.8v1.8M144.1 104.6l.6 .6v.7M144.1 114.8l.6 .5M144.2 114.8h1.7M144.2 106.4h1.9M144.2 116.5l1.8 .1M144.2 106.4h1.7M144.2 104.7h1.7M144.2 114.9h1.7M144.3 116.5h1.6"/>
<path d="M144.3 114.9h1.5M144.3 106.3h1.5M144.3 104.8h1.5M144.3 116.5h1.5M144.3 116.4h1.4M144.3 115h1.4M144.4 115h1.3M144.4 106.2h1.3M144.4 116.4h1.2M144.4 106.2h1.2M144.4 115.1h1.2M144.5 116.3h1.1"/>
<path d="M144.5 104.9h1.1M144.5 115.1h1.1M144.5 106.1h1.1M144.5 116.2h1M144.5 106.1h1M144.5 105h1M144.5 115.2h1M144.6 116.2h.9M144.6 115.2h.9M144.6 106h.9M144.6 105.1h.9M144.6 116.1h.9"/>
<path d="M144.7 116.1h.7M144.7 115.3h.8M144.7 105.2h.7M144.7 115.3v.8l-.6 .5M144.7 105.9l-.6 .6M144.7 116h.7M144.7 115.9h.7M144.7 115.8h.7M144.7 115.7h.7M144.7 115.6h.7M144.7 115.5h.7M144.7 115.4h.7"/>
<path d="M144.7 105.9h.7M144.7 105.8l.7 .1M144.7 105.8h.7M144.7 105.7h.7M144.7 105.6h.7M144.7 105.5h.7M144.7 105.4h.7M144.7 105.3h.7M144.8 108.8l.6 .3M144.8 108.9h1M144.9 108.9h1M145 109h.9"/>
<path d="M145.2 109h.6M145.4 105.5v.1M145.4 108v.2M145.4 115.6v.2M145.4 118.2v.1M145.4 118.3v.2M145.4 105.6v.2M145.4 108.2v.2M145.4 115.8v.2M145.4 115.5h-.7M145.4 107.9h-21.6M145.4 105.4h-.7"/>
<path d="M145.4 118v.2M145.4 118.5l.3 .5M145.4 105.3v.2M145.4 105.8l.1 .2M145.4 107.8v.2M145.4 108.4l.1 .1M145.4 115.4v.2M145.4 116l.1 .1M145.4 115.4h-.7M145.4 107.8h-21.6M145.4 105.3h-.7M145.4 107.7l-21.6 .1"/>
<path d="M145.4 105.2h-.7M145.4 115.3h-.7M145.4 107.7h-21.6M145.5 105.1l-.1 .2M145.5 106l.1 .1M145.5 107.6l-.1 .2M145.5 108.5l.1 .2M145.5 116.1l.2 .3M145.5 107.6l-21.7 .1M145.5 117.8h-21.7M145.5 117.7h-21.7M145.5 107.5l-21.7 .1"/>
<path d="M145.6 117.6l-.2 .4M145.6 106.1l.6 .4M145.6 107.5l-.1 .1M145.6 108.7l.3 .2M145.6 115.1l-.2 .3M145.6 117.6l-21.8 .1M145.6 107.5h-21.8M145.6 104.5l.3 .2M145.6 114.7l.3 .1M145.6 117.6h-21.8M145.6 107.4l-21.8 .1M145.6 104.9h-1.2"/>
<path d="M145.7 117.5l-21.9 .1M145.7 107.4h-21.9M145.7 117.5l-.1 .1M145.7 119l.3 .1M145.7 104.8l-.2 .3M145.7 115l-.1 .1M145.7 116.4l.5 .2M145.7 104.8h-1.3M145.7 117.5h-21.9M145.8 107.3l-22 .1M145.8 117.4l-22 .1M145.8 107.3h-22"/>
<path d="M145.9 117.4h-22.1M145.9 104.7h.1M145.9 104.7l-.2 .1M145.9 108.9l.1 .1M145.9 108.9l-.6 .2M145.9 114.8l.1 .1M145.9 114.8l-.2 .2M146 107.2l-22.2 .1M146 119.1l.2 .1M146.1 117.3l-22.3 .1M146.1 107.2h-22.3M146.2 117.3l-.5 .2"/>
<path d="M146.2 107.1l-.6 .4M146.9 105.5v1M146.9 107.1v1M146.9 115.7v.9M146.9 117.3v1.9M146.9 119.1h.1M146.9 119h.1M146.9 118.9h.1M146.9 118.8h.1M146.9 118.7h.1M146.9 118.6h.1M146.9 118.5h.1"/>
<path d="M146.9 118.4h.1M146.9 118.3h.1M146.9 118.1h.1M146.9 118h.1M146.9 117.9h.1M146.9 117.8h.1M146.9 117.7h.1M146.9 117.6h.1M146.9 117.5h.1M146.9 117.4h.1M146.9 117.3h.1M146.9 116.5h.1"/>
<path d="M146.9 116.4h.1M146.9 116.3h.1M146.9 116.2h.1M146.9 116.1h.1M146.9 116h.1M146.9 115.9h.1M146.9 115.8h.1M146.9 115.7h.1M146.9 108h.1M146.9 107.9h.1M146.9 107.8h.1M146.9 107.7h.1"/>
<path d="M146.9 107.6h.1M146.9 107.5h.1M146.9 107.4h.1M146.9 107.3h.1M146.9 107.2h.1M146.9 106.4h.1M146.9 106.3h.1M146.9 106.2h.1M146.9 106.1h.1M146.9 106h.1M146.9 105.9h.1M146.9 105.8h.1"/>
<path d="M146.9 105.7h.1M146.9 105.6h.1M147 107.1v1h-23.2M147 115.7v.9M147 117.3v1.9M147.7 117.3l.6 .3M147.7 107.1l.6 .4M147.7 106.4h.6M147.8 107.2h.5M147.8 117.3h4.7M147.8 119.1h4.7M147.9 116.6h4.5"/>
<path d="M147.9 107.2h.4M147.9 114.8l.4 .3M147.9 114.8l.1 .1M147.9 106.4h.4M148 117.4h4.4M148 114.9h4.4M148 119.1h4.4M148 116.5h4.4M148 119.1l-.3 .1M148 116.5l-.3 .1M148.1 117.4h4.3M148.1 114.9h4.3"/>
<path d="M148.1 107.3h.2M148.1 106.3h.2M148.1 119h4.3M148.1 116.5h4.3M148.1 117.5h4.3M148.1 115h4.3M148.2 119h4.2M148.2 116.4h4.2M148.2 117.5h4.2M148.2 115h4.2M148.2 107.4h.1M148.2 106.2h.1"/>
<path d="M148.2 118.9h4.2M148.3 116.4h4.1M148.3 107.4h.1M148.3 106.2h.1M148.3 106.2v1.2M148.3 106.2l-.6 .3M148.3 107.1h-24.5M148.3 117.6h4.1M148.3 115.1h4.1M148.3 118.9h4M148.3 116.3h4M148.3 117.6l.2 .4"/>
<path d="M148.3 118.8l-.3 .3M148.3 116.3l-.3 .2M148.3 115.1l.2 .3M148.3 117.6h4M148.3 115.1h4M148.3 118.8h4M148.3 116.2h4M148.4 117.7h3.9M148.4 115.2h3.9M148.4 118.7h3.9M148.4 117.8h3.9M148.4 116.2h3.9"/>
<path d="M148.4 118.7l-.1 .1M148.4 116.1l-.1 .2M148.4 118.6h3.9M148.4 116.1h3.9M148.4 115.3h3.9M148.4 118.6h3.8M148.4 117.9h3.8M148.5 117.9h3.7M148.5 116h3.7M148.5 115.4h3.7M148.5 118v.2M148.5 118.5l-.1 .2"/>
<path d="M148.5 116l-.1 .1M148.5 115.4v.2M148.5 118.5h3.7M148.5 118h3.7M148.5 118.4h3.7M148.5 118.1h3.7M148.5 115.9h3.7M148.5 115.8h3.7M148.5 115.5h3.7M148.5 115.6v.2M148.5 118.2v.1M148.5 118.3v.2"/>
<path d="M148.5 115.8v.2M148.5 118.3h3.7M148.5 115.7h3.7M148.5 115.6h3.7M148.7 114.4h4.1M148.8 114.3h3.9M148.9 114.2h3.7M149 114.1h3.5M149 114.1l-.5 .5-.6 .2M149 112.2l.3 .6M149 112.2h3.5M149.1 114h3.3"/>
<path d="M149.1 113.9h3.3M149.1 112.4h3.3M149.1 113.8h3.3M149.1 112.5h3.3M149.2 113.7h3.1M149.2 112.6h3.1M149.2 113.6h3.1M149.2 112.7h3.1M149.2 113.5h3.1M149.2 112.8h3.1M149.3 112.8v.7M149.3 113.5l-.3 .6"/>
<path d="M149.3 113.5h2.9M149.3 113.4h2.9M149.3 113.3h2.9M149.3 113.2h2.9M149.3 113.1h2.9M149.3 113h2.9M149.3 112.9h2.9M149.3 112.8h2.9M152.2 118.2l-28.4 .1M152.2 115.7h-28.4M152.2 112.8v.7M152.2 115.4v.6"/>
<path d="M152.2 117.9v.7M152.2 113.5l.3 .6M152.2 116l.3 .6M152.2 118.6l.3 .6 .5 .5M152.3 112.6h-3.1M152.4 112.5h-3.3M152.4 112.4h-3.3M152.4 112.3h-3.3M152.5 114.8h-4.6M152.5 112.2l-3.5 .1M152.5 117.3h-28.7M152.5 114.7l-4.4 .1"/>
<path d="M152.5 112.2l-.3 .6M152.5 114.1l.3 .3M152.5 114.7l-.3 .7M152.5 116.6l.3 .4M152.5 117.3l-.3 .6M152.5 112.2h-3.5M152.5 114.7h-4.3M152.5 117.2h-28.7M152.6 114.6l-4.3 .1M152.7 117.1l-28.9 .1M152.7 114.6h-4.3M152.7 117.1h-28.9"/>
<path d="M152.7 114.5l-4.1 .1M152.8 117l-29 .1M152.8 114.5h-4.2M152.8 114.4l-.3 .3M152.8 117l-.3 .3M152.8 117h-29M152.8 114.4h-4.1M153 119.7l.6 .2M155.6 119.9h18.5M155.8 119.8h18.3M155.9 119.8h18.2M155.9 119.8l-.3 .1"/>
<path d="M156.6 109.6h10.2M156.6 109.7l.3 .6M156.6 109.7l10.2-.1v1.4M156.7 109.7h10.1M156.7 109.8h10.1M156.7 109.9h10.1M156.7 101.2h17.4M156.7 111.3h10.2M156.7 101.1h17.4M156.8 111.3h10.1M156.8 110h10M156.8 101.1h17.3"/>
<path d="M156.8 111.2h10.1M156.8 101h17.3M156.8 111.1h10M156.8 110.1h10M156.8 100.9h17.3M156.8 111l10 .1M156.8 110.2h10M156.8 100h17.3M156.9 111h9.9M156.9 110.2h9.9M156.9 100.8h17.2M156.9 100.1h17.2"/>
<path d="M156.9 111l-.3 .6h1.5M156.9 100.1l-.2 1.1h17.4M156.9 110.3v.7M156.9 110.9h9.9M156.9 110.8h9.9M156.9 110.7h9.9M156.9 110.6h9.9M156.9 110.5h9.9M156.9 110.4h9.9M156.9 110.3h9.9M156.9 100.7h17.2M156.9 100.6h17.2"/>
<path d="M156.9 100.5h17.2M156.9 100.4h17.2M156.9 100.3h17.2M156.9 100.2h17.2M157.8 101.2l.4 .2M157.9 101.3h.6M158 101.3h.4M158.2 101.4h.1M158.2 111.6h-1.6M158.4 111.5h-1.8M158.5 111.5h-1.8M158.6 111.4h-1.9"/>
<path d="M158.6 111.4l-.6 .2M158.6 101.2l-.4 .2M160.6 111.4l.7 .3 .5 .4M160.6 101.2l.7 .3M160.7 111.4h6.2M160.7 101.3h13.4M160.8 111.5h6.2M160.9 101.3h13.2M160.9 111.5h6.1M161 101.4h13.1M161.1 111.6h5.9M161.1 101.4h13"/>
<path d="M161.2 111.6l5.9 .1M161.3 101.5l.5 .5 .3 .6M161.3 101.5h12.8M161.3 111.7h5.8M161.3 111.7l5.9 .1M161.4 101.6h12.7M161.4 111.8h5.8M161.4 111.8h5.9M161.5 101.7h12.6M161.5 111.9h5.8M161.5 111.9l5.9 .1M161.6 101.8h12.5"/>
<path d="M161.6 112h5.8M161.6 101.9h12.5M161.6 112l5.9 .1M161.7 101.9h12.4M161.7 112.1h5.8M161.7 102h12.4M161.8 112.1l5.9 .1M161.8 114.2h.1M161.8 112.1l.3 .7M161.8 102h12.3M161.8 112.2h6M161.8 102.1h12.3"/>
<path d="M161.8 112.2l6.1 .1M161.8 112.3h6.2M161.8 102.2h12.3M161.9 112.4h12.2M161.9 102.2h12.2M161.9 113.9h12.2M161.9 102.3h12.2M161.9 112.5h12.2M161.9 113.8h12.2M161.9 103.6h5.4M161.9 102.4h12.2M161.9 113.7h12.2"/>
<path d="M161.9 112.6h12.2M162 113.7h12.1M162 112.6h12.1M162 102.5h12.1M162 102.4h12.1M162 113.6h12.1M162 112.7h12.1M162 102.6h12.1M162 112.8h12.1M162.1 113.5l-.3 .7M162.1 102.6v.8M162.1 112.8v.7"/>
<path d="M162.1 103.4l-.3 .6h.5M162.1 113.5h12M162.1 113.4h12M162.1 113.3h12M162.1 113.2h12M162.1 113.1h12M162.1 113h12M162.1 112.9h12M162.1 112.8h12M162.1 103.1h12M162.1 103h12M162.1 102.9h12"/>
<path d="M162.1 102.8h12M162.1 102.7h12M162.4 103.9h-.6M162.5 103.9h-.7M162.6 103.8h-.8M162.8 103.8l-.6 .2M164.1 114.2h-2.3M164.3 114.1h-2.5M164.4 114l-2.6 .1M164.4 103.8l.7 .2M164.5 114h-2.7M164.5 103.8h2.6"/>
<path d="M164.6 113.9l-2.8 .1M164.7 113.9l-.6 .3M164.7 103.9h2.3M164.8 103.9h2.2M164.9 104h2.1M165.1 104l.5 .5 .3 .7M165.1 104h1.9M165.1 104.1h1.8M165.2 104.1h1.7M165.2 104.2h1.7M165.3 104.2h1.6M165.3 104.3h1.6"/>
<path d="M165.4 104.4h1.4M165.5 104.5h1.3M165.6 106.5h1.2M165.6 104.6h1.2M165.6 106.4h1.2M165.6 104.7h1.2M165.7 106.4h1.1M165.7 104.7h1.1M165.7 106.3h1.1M165.7 104.8h1.1M165.7 106.2h1.1M165.7 104.9h1.1"/>
<path d="M165.8 106.1h1M165.8 105h1M165.8 106h1M165.8 105.1h1M165.8 105.9h1M165.8 105.2h1M165.9 105.5h.9M165.9 105.9l-.3 .7h1.2M165.9 105.2v.7M165.9 105.8h.9M165.9 105.7h.9M165.9 105.6h.9"/>
<path d="M165.9 105.4h.9M165.9 105.3h.9M165.9 105.2h.9M166.3 113.9l1 .5M166.4 113.9h1.7M166.5 114h1.5M166.6 114h1.3M166.8 104.5v2M166.8 111l.2 .6 .5 .5M166.8 106.5v.1M166.8 114.1h.9M166.9 114.2h.7"/>
<path d="M166.9 111.4h-10.2M167 114.2h.5M167 114.3h.4M167.1 114.3h.3M167.2 114.4h.2M167.2 103.8h-5.3M167.2 103.7h-5.3M167.2 114.4h.1M167.3 103.7h-5.4M167.4 103.5l-5.5 .1M167.4 103.5h-5.4M167.5 103.4l-5.5 .1"/>
<path d="M167.5 112.1l.7 .3M167.5 103.4h-5.5M167.7 119.7h6.4M167.7 103.3l-5.7 .1M167.8 119.7h6.3M167.8 103.3h-5.7M167.9 119.6h6.2M167.9 103.2l-5.8 .1M168 119.5h6.1M168 103.2h-5.9M168.1 119.5h6M168.2 113.9l-.9 .5"/>
<path d="M168.2 103.1l-.7 .3-.5 .5-.2 .6M168.2 119.4h5.9M168.3 119.4h5.8M168.3 119.3h5.8M168.4 119.3h5.7M168.4 119.2h5.7M168.5 119.2h5.6M168.5 119.1h5.6M168.6 119.1h5.5M168.6 119h5.5M168.7 119h5.4M168.7 118.9h5.4"/>
<path d="M168.8 118.9h5.3M168.8 118.8h5.3M168.9 113.9l.6 .3 .5 .5 .3 .6M168.9 103.1l.6 .3M168.9 118.7h5.2M168.9 113.9h5.2M169 118.6h5.1M169 103.2h5.1M169 112.3h5.1M169.1 114h5M169.1 118.5h5M169.1 112.3h5"/>
<path d="M169.1 103.2h5M169.2 114h4.9M169.2 118.4h4.9M169.2 112.2h4.9M169.3 103.3h4.8M169.3 118.3h4.8M169.3 114.1h4.8M169.4 112.2h4.7M169.4 103.3h4.7M169.4 118.3h4.7M169.4 118.2h4.7M169.4 114.2h4.7"/>
<path d="M169.5 118.2l-1.4 1.3-.5 .3M169.5 118.2h4.6M169.5 112.1l-.6 .3M169.5 103.4l.5 .5 .3 .6M169.5 112.1h4.6M169.5 103.4h4.6M169.5 114.2h4.6M169.6 118.1h4.5M169.6 112.1h4.5M169.6 103.4h4.5M169.6 114.3h4.5M169.6 112h4.5"/>
<path d="M169.6 103.5h4.5M169.7 114.3h4.4M169.7 118h4.4M169.7 112h4.4M169.7 103.5h4.4M169.7 114.4h4.4M169.7 111.9h4.4M169.7 103.6h4.4M169.8 114.4h4.3M169.8 117.9h4.3M169.8 111.9h4.3M169.8 103.7h4.3"/>
<path d="M169.8 114.5h4.3M169.8 111.8h4.3M169.9 114.5h4.2M169.9 103.8h4.2M169.9 117.8h4.2M169.9 111.8h4.2M169.9 114.6h4.2M169.9 117.7h4.2M169.9 111.7h4.2M170 114.6h4.1M170 111.7h4.1M170 117.7h4.1"/>
<path d="M170 103.9h4.1M170 114.7h4.1M170 117.6h4.1M170 111.6h4.1M170.1 114.7h4M170.1 107.1v1.6M170.1 107.1h4M170.1 108.1h4M170.1 108.7l.2 .6M170.1 104h4M170.1 117.6h4M170.1 111.5h4"/>
<path d="M170.1 108.7h4M170.1 108.6h4M170.1 108.5h4M170.1 108.4h4M170.1 108.3h4M170.1 108.2h4M170.1 108h4M170.1 107.9h4M170.1 107.8h4M170.1 107.7h4M170.1 107.6h4M170.1 107.5h4"/>
<path d="M170.1 107.4h4M170.1 107.3h4M170.1 107.2h4M170.1 108.8h4M170.1 117.5h4M170.1 114.8h4M170.1 114.9h4M170.1 111.4h4M170.1 107h4M170.1 104.1h4M170.1 117.4h4M170.1 108.9h4"/>
<path d="M170.1 115h4M170.1 106.9h4M170.1 104.2h4M170.2 117.3h3.9M170.2 115h3.9M170.2 111.3h3.9M170.2 109h3.9M170.2 106.8h3.9M170.2 115.1h3.9M170.2 104.3h3.9M170.2 104.2h3.9M170.2 109.1h3.9"/>
<path d="M170.2 111.2h3.9M170.2 106.7h3.9M170.2 117.2h3.9M170.2 115.2h3.9M170.2 111.1h3.9M170.2 104.4h3.9M170.2 109.2h3.9M170.2 106.6h3.9M170.3 106.6h3.8M170.3 117.1h3.8M170.3 115.3h3.8M170.3 111h3.8"/>
<path d="M170.3 109.2h3.8M170.3 104.5h3.8M170.3 106.5h3.8M170.3 109.3h3.8M170.3 116.6h3.8M170.3 115.7h3.8M170.3 115.6h3.8M170.3 105.5h3.8M170.3 104.6h3.8M170.3 104.5v2M170.3 109.3v1.7M170.3 115.3v1.7l-.3 .6-.5 .6"/>
<path d="M170.3 116.7h3.8M170.3 109.6h3.8M170.3 111l-.3 .6-.5 .5M170.3 106.5l-.2 .6M170.3 117h3.8M170.3 116.9h3.8M170.3 116.8h3.8M170.3 116.5h3.8M170.3 116.4h3.8M170.3 116.3h3.8M170.3 116.2h3.8M170.3 116.1h3.8"/>
<path d="M170.3 116h3.8M170.3 115.9h3.8M170.3 115.8h3.8M170.3 115.5h3.8M170.3 115.4h3.8M170.3 110.9h3.8M170.3 110.8h3.8M170.3 110.7h3.8M170.3 110.6h3.8M170.3 110.5h3.8M170.3 110.4h3.8M170.3 110.3h3.8"/>
<path d="M170.3 110.2h3.8M170.3 110.1h3.8M170.3 110h3.8M170.3 109.9h3.8M170.3 109.8h3.8M170.3 109.7h3.8M170.3 109.5h3.8M170.3 109.4h3.8M170.3 106.4h3.8M170.3 106.3h3.8M170.3 106.2h3.8M170.3 106.1h3.8"/>
<path d="M170.3 106h3.8M170.3 105.9h3.8M170.3 105.8h3.8M170.3 105.7h3.8M170.3 105.6h3.8M170.3 105.4h3.8M170.3 105.3h3.8M170.3 105.2h3.8M170.3 105.1h3.8M170.3 105h3.8M170.3 104.9h3.8M170.3 104.8h3.8"/>
<path d="M170.3 104.7h3.8M174.1 113.9h-12.2M174.1 103.1l-12 .1M123.8 140h4.1M123.8 139.9l4 .1M123.8 139.9h3.9M123.8 139.8h3.9M123.8 139.8h3.8M123.8 139.7h3.8M123.8 139.7h3.7M123.8 139.6h3.6M123.8 139.5h3.5"/>
<path d="M123.8 139.4l3.5 .1M123.8 139.4h3.4M123.8 139.3h3.4M123.8 139.3h3.3M123.8 139.2h3.3M123.8 139.1h3.3M123.8 139.1h3.2M123.8 139h3.2M123.8 138.9h3.1M123.8 138.8h3.1M123.8 138.7l3.1 .1M123.8 138.7h3"/>
<path d="M123.8 138.6h3M123.8 138.5l3 .1M123.8 138.5h3M123.8 138.4h2.9M123.8 138.3h2.9M123.8 138.2h2.9M123.8 138.1h2.9M123.8 138h2.9M123.8 137.9h2.9M123.8 137.8h2.9M123.8 137.7h2.9M123.8 137.6h2.9"/>
<path d="M123.8 137.5h2.9M123.8 137.4h2.9M123.8 137.3h2.9M123.8 137.2h2.9M123.8 137.1h2.9M123.8 137.1h3M123.8 137h3M123.8 136.9h3M123.8 136.8h3M123.8 136.4h3.2M123.8 136.3h3.3M123.8 135.1h50.3"/>
<path d="M123.8 135h50.3M123.8 134.9h50.3M123.8 134.8h50.3M123.8 134.7h50.3M123.8 134.6h50.3M123.8 134.5h50.3M123.8 134.4h50.3M123.8 134.3h50.3M123.8 134.2h50.3M123.8 134.1h50.3M123.8 134h50.3M123.8 133.9h50.3"/>
<path d="M123.8 133.8h50.3M123.8 133.7h50.3M123.8 133.6h50.3M123.8 133.5h50.3M123.8 133.4h50.3M123.8 133.3h50.3M123.8 133.2h50.3M123.8 133.1h50.3M123.8 133h50.3M123.8 132.9h50.3M123.8 132.8h50.3M123.8 132.7h50.3"/>
<path d="M123.8 132.6h50.3M123.8 132.5h50.3M123.8 132.4h50.3M123.8 132.3h50.3M123.8 132.2h50.3M123.8 132.1h50.3M123.8 132h50.3M123.8 131.9h50.3M123.8 131.8h50.3M123.8 131.7h50.3M123.8 131.6h50.3M123.8 131.5h50.3"/>
<path d="M123.8 131.4h50.3M123.8 131.3h50.3M123.8 131.2h50.3M123.8 131.1h50.3M123.8 131h50.3M123.8 130.9h50.3M123.8 130.8h50.3M123.8 130.7h50.3M123.8 130.6h50.3M123.8 130.5h50.3M123.8 130.4h50.3M123.8 130.3h50.3"/>
<path d="M123.8 130.2h50.3M123.8 130.1h50.3M123.8 130h50.3M123.8 129.9h50.3M123.8 129.8h50.3M123.8 129.7h50.3M123.8 129.6h50.3M123.8 129.5h50.3M123.8 129.4h50.3M123.8 129.3h50.3M123.8 129.2h50.3M123.8 129.1h50.3"/>
<path d="M123.8 129h50.3M123.8 128.9h50.3M123.8 128.8h50.3M123.8 128.7h50.3M123.8 128.6h50.3M123.8 128.5h50.3M123.8 128.4h50.3M123.8 128.3h50.3M123.8 128.2h50.3M123.8 128.1h50.3M123.8 128h50.3M123.8 127.9h50.3"/>
<path d="M123.8 127.8h50.3M123.8 127.7h50.3M123.8 127.6h50.3M123.8 127.5h50.3M123.8 127.4h50.3M123.8 127.3h50.3M123.8 127.2h50.3M123.8 127.1h50.3M123.8 127h50.3M123.8 126.9h50.3M123.8 126.8h50.3M123.8 126.7h50.3"/>
<path d="M123.8 126.6h50.3M123.8 126.5h50.3M123.8 126.4h50.3M123.8 126.3h50.3M123.8 126.2h50.3M123.8 126.1h50.3M123.8 126h50.3M123.8 125.9h50.3M123.8 125.8h50.3M123.8 125.7h50.3M123.8 125.6h50.3M123.8 125.5h50.3"/>
<path d="M123.8 125.4h50.3M123.8 125.3h50.3M123.8 125.2h50.3M123.8 125.1h50.3M123.8 125h50.3M123.8 124.9h50.3M123.8 124.8h50.3M123.8 124.7h50.3M123.8 124.6h50.3M123.8 124.5h50.3M123.8 124.4h50.3M123.8 124.3h50.3"/>
<path d="M123.8 124.2h50.3M123.8 124.1h50.3M123.8 124h50.3M123.8 123.9h50.3M123.8 123.8h50.3M123.8 123.7h50.3M123.8 123.6h50.3M123.8 123.5h50.3M123.8 123.4h50.3M123.8 123.3h50.3M123.8 123.2h50.3M123.8 123.1h50.3"/>
<path d="M123.8 123h50.3M123.8 122.9h50.3M123.8 122.8h50.3M123.8 122.7h50.3M123.8 122.6h50.3M123.8 122.5h50.3M123.8 122.4h50.3M123.8 122.3h50.3M123.8 122.2h50.3M123.8 122.1h50.3M123.8 122h50.3M123.8 121.9h50.3"/>
<path d="M123.8 121.8h50.3M123.8 121.7h50.3M123.8 121.6h50.3M123.8 121.5h50.3M123.8 121.4h50.3M123.8 121.3h50.3M123.8 121.2h50.3M123.8 121.1h50.3M123.8 121h50.3M123.8 120.9h50.3M123.8 120.8h50.3M123.8 120.7h50.3"/>
<path d="M123.8 120.6h50.3M123.8 120.5h50.3M123.8 120.4h50.3M123.8 120.3h50.3M123.8 120.2h50.3M123.8 120.1h50.3M126.7 137.4v.7M126.7 138.1l.1 .7M126.7 137.3h-2.9M126.8 136.9l-3 .1M126.8 136.8l-.1 .6M126.8 138.8l.4 .6"/>
<path d="M126.9 136.7l-3.1 .1M126.9 136.7h-3.1M126.9 136.6l-3.1 .1M126.9 136.6h-3.1M127 136.5h-3.2M127.1 136.4h-3.3M127.1 136.2l-3.3 .1M127.2 136.2h-3.4M127.2 136.2l-.4 .6M127.2 139.4l1.1 .8M127.2 136.1l-3.4 .1M127.2 136.1h-3.4"/>
<path d="M127.3 136l-3.5 .1M127.3 136h-3.5M127.4 135.9l-3.6 .1M127.5 135.9h-3.7M127.5 135.8l-3.7 .1M127.6 135.8h-3.8M127.6 135.7l-3.8 .1M127.7 135.7h-3.9M127.8 135.6l-4 .1M127.8 135.6h-4M128 135.5l-4.2 .1M128 135.5h-4.2"/>
<path d="M128.1 135.4h-4.3M128.2 135.4h-4.4M128.4 135.3h-4.6M128.5 135.3h-4.7M128.8 135.2h-5M128.9 135.1l-1.2 .6-.5 .5M129.6 135.1l1.3 .6 .5 .5M129.8 135.2h36.1M130 135.3h35.7M130.2 135.3h35.3M130.4 135.4h34.9M130.6 135.5h34.6"/>
<path d="M130.6 135.5h34.5M130.7 140h34.3M130.7 135.6h34.3M130.8 135.6h34.1M130.9 139.9h33.9M130.9 139.9l-.6 .3M130.9 139.8h33.9M130.9 135.7h33.9M131 135.7h33.8M131 139.8h33.7M131 139.7h33.7M131 135.8h33.7"/>
<path d="M131.1 135.8h33.6M131.1 139.7h33.5M131.1 139.6h33.5M131.1 135.9h33.5M131.2 135.9h33.3M131.2 139.6h33.3M131.2 139.5h33.3M131.2 136h33.3M131.3 136h33.1M131.3 139.5h33.1M131.3 139.4h33.1M131.3 136.1h33.1"/>
<path d="M131.4 136.2l.3 .6M131.4 136.1h32.9M131.4 139.3l32.9 .1M131.4 139.3h32.9M131.4 136.2h32.9M131.5 139.2l32.8 .1M131.5 139.2h32.7M131.5 139.1h32.7M131.6 139.1h32.6M131.6 136.4h32.6M131.6 136.5h32.5M131.6 139h32.5"/>
<path d="M131.6 138.9h32.5M131.7 138.9h32.3M131.7 136.6h32.3M131.7 136.7h32.3M131.7 138.8h32.3M131.7 136.8l.2 .6M131.7 138.8l-.8 1.1M131.7 138.7h32.3M131.8 138.7h32.2M131.8 138.6l32.2 .1M131.8 138.6h32.1M131.8 136.9h32.1"/>
<path d="M131.8 138.5h32.1M131.8 138.4h32.1M131.8 137.1h32.1M131.8 138.3h32.1M131.9 138.3h32M131.9 137.2h32M131.9 138.2h31.9M131.9 137.4v.7M131.9 138.1l-.2 .7M131.9 138.1h31.9M131.9 138h31.9M131.9 137.9h31.9"/>
<path d="M131.9 137.8h31.9M131.9 137.7h31.9M131.9 137.6h31.9M131.9 137.5h31.9M131.9 137.4h31.9M163.8 137.4v.7M163.8 138.1l.2 .7M163.8 137.3l-31.9 .1M163.9 137.3h-32M163.9 137.2h-32.1M163.9 137h-32.1M163.9 136.9l-32.1 .1"/>
<path d="M164 136.8l-32.2 .1M164 136.8l-.2 .6M164 138.8l.8 1.1M164 136.8h-32.3M164.1 136.6h-32.5M164.2 136.4h-32.7M164.2 136.3h-32.7M164.3 136.2l-32.9 .1M164.3 136.2l-.3 .6M164.8 139.9l1.3 .5M166.1 135.1l-1.3 .6-.5 .5M166.8 135.1a2.54 2.54 0 0 1 2.1 1.7"/>
<path d="M166.9 135.2h7.2M167.2 135.3h6.9M167.4 135.3h6.7M167.5 135.4h6.6M167.6 135.4h6.5M167.7 135.5h6.4M167.8 140h6.3M167.9 135.6h6.2M167.9 140h6.2M168 135.6h6.1M168 139.9h6.1M168 139.9l-.6 .3"/>
<path d="M168.1 139.8h6M168.1 135.7h6M168.1 135.8h6M168.2 139.7h5.9M168.2 135.8h5.9M168.3 135.9h5.8M168.3 139.6h5.8M168.4 139.5h5.7M168.4 136h5.7M168.5 136.1h5.6M168.5 139.4h5.6M168.6 139.3h5.5"/>
<path d="M168.6 136.2h5.5M168.6 136.3h5.5M168.6 139.2h5.5M168.6 136.4h5.5M168.7 139.1h5.4M168.7 136.4h5.4M168.7 136.5h5.4M168.7 139h5.4M168.8 136.6h5.3M168.8 138.9h5.3M168.8 136.7h5.3M168.8 138.8h5.3"/>
<path d="M168.9 136.8l.2 .6M168.9 138.8l-.9 1.1M168.9 138.8h5.2M168.9 136.7h5.2M168.9 138.7h5.2M168.9 136.8h5.2M168.9 138.6h5.2M168.9 136.9h5.2M169 138.5h5.1M169 137.1h5.1M169 137h5.1M169 138.4h5.1"/>
<path d="M169 138.3h5.1M169 137.2h5.1M169 138.2h5.1M169 137.3h5.1M169 137.4h5.1M169.1 137.4v.7M169.1 138.1l-.2 .7M169.1 138.1h5M169.1 138h5M169.1 137.9h5M169.1 137.8h5M169.1 137.7h5"/>
<path d="M169.1 137.6h5M169.1 137.5h5M169.1 137.4h5M174.1 135.1l-50.3 .1M123.8 140.4h50.3M123.8 143.2h50.3M123.8 143.1h50.3M123.8 143h50.3M123.8 142.9h50.3M123.8 142.8h50.3M123.8 142.7h50.3M123.8 142.6h50.3"/>
<path d="M123.8 142.5h50.3M123.8 142.4h50.3M123.8 142.3h50.3M123.8 142.2h50.3M123.8 142.1h50.3M123.8 142h50.3M123.8 141.9h50.3M123.8 141.8h50.3M123.8 141.7h50.3M123.8 141.6h50.3M123.8 141.5h50.3M123.8 141.4h50.3"/>
<path d="M123.8 141.3h50.3M123.8 141.2h50.3M123.8 141.1h50.3M123.8 141h50.3M123.8 140.9h50.3M123.8 140.8h50.3M123.8 140.7h50.3M123.8 140.6h50.3M123.8 140.5h50.3M123.8 140.3l5.1 .1M123.8 140.3h4.8M123.8 140.2l4.7 .1"/>
<path d="M123.8 140.2h4.5M123.8 140.1l4.4 .1M123.8 140.1h4.3M123.8 140l4.2 .1M128.3 140.2l.6 .2M129.7 140.4h36.3M129.9 140.3h35.9M130.1 140.3h35.5M130.3 140.2l-.7 .2M130.3 140.2h35.1M130.4 140.2h34.9M130.5 140.1h34.7"/>
<path d="M130.6 140.1h34.5M166.9 140.4h7.2M167.1 140.3h7M167.2 140.3h6.9M167.4 140.2l-.6 .2M167.4 140.2h6.7M167.5 140.2h6.6M167.6 140.1h6.5M167.7 140.1h6.4"/>
</g>
<circle cx="136.1" cy="80.5" r=".66" fill="#000" stroke="#000" stroke-width=".21"/>
<circle cx="136.1" cy="80.5" r=".4" fill="#fff" stroke="#000" stroke-width=".21"/>
<circle cx="136.1" cy="83" r=".66" fill="#000" stroke="#000" stroke-width=".21"/>
<circle cx="136.1" cy="83" r=".4" fill="#fff" stroke="#000" stroke-width=".21"/>
<circle cx="143.8" cy="83" r=".66" fill="#000" stroke="#000" stroke-width=".21"/>
<circle cx="143.8" cy="83" r=".4" fill="#fff" stroke="#000" stroke-width=".21"/>
<circle cx="143.8" cy="80.5" r=".66" fill="#000" stroke="#000" stroke-width=".21"/>
<circle cx="143.8" cy="80.5" r=".4" fill="#fff" stroke="#000" stroke-width=".21"/>
<circle cx="136.1" cy="85.5" r=".66" fill="#000" stroke="#000" stroke-width=".21"/>
<circle cx="136.1" cy="85.5" r=".4" fill="#fff" stroke="#000" stroke-width=".21"/>
<circle cx="136.1" cy="88.1" r=".66" fill="#000" stroke="#000" stroke-width=".21"/>
<circle cx="136.1" cy="88.1" r=".4" fill="#fff" stroke="#000" stroke-width=".21"/>
<circle cx="143.8" cy="85.5" r=".66" fill="#000" stroke="#000" stroke-width=".21"/>
<circle cx="143.8" cy="85.5" r=".4" fill="#fff" stroke="#000" stroke-width=".21"/>
<circle cx="143.8" cy="88.1" r=".66" fill="#000" stroke="#000" stroke-width=".21"/>
<circle cx="143.8" cy="88.1" r=".4" fill="#fff" stroke="#000" stroke-width=".21"/>
<circle cx="146.9" cy="91.2" r=".71" fill="#000" stroke="#000" stroke-width=".21"/>
<circle cx="146.9" cy="91.2" r=".4" fill="#fff" stroke="#000" stroke-width=".21"/>
<circle cx="146.9" cy="96.3" r=".71" fill="#000" stroke="#000" stroke-width=".21"/>
<circle cx="146.9" cy="96.3" r=".4" fill="#fff" stroke="#000" stroke-width=".21"/>
<path d="M146.3 80.5h1.3" fill="none" stroke="#000" stroke-width="1.3"/>
<circle cx="146.9" cy="80.5" r=".4" fill="#fff" stroke="#000" stroke-width=".21"/>
<path d="M146.3 83h1.3" fill="none" stroke="#000" stroke-width="1.3"/>
<circle cx="146.9" cy="83" r=".4" fill="#fff" stroke="#000" stroke-width=".21"/>
<path d="M153.9 83h1.3" fill="none" stroke="#000" stroke-width="1.3"/>
<circle cx="154.6" cy="83" r=".4" fill="#fff" stroke="#000" stroke-width=".21"/>
<path d="M153.9 80.5h1.3" fill="none" stroke="#000" stroke-width="1.3"/>
<circle cx="154.6" cy="80.5" r=".4" fill="#fff" stroke="#000" stroke-width=".21"/>
<path d="M146.3 85.5h1.3" fill="none" stroke="#000" stroke-width="1.3"/>
<circle cx="146.9" cy="85.5" r=".4" fill="#fff" stroke="#000" stroke-width=".21"/>
<path d="M146.3 88.1h1.3" fill="none" stroke="#000" stroke-width="1.3"/>
<circle cx="146.9" cy="88.1" r=".4" fill="#fff" stroke="#000" stroke-width=".21"/>
<path d="M153.9 85.5h1.3" fill="none" stroke="#000" stroke-width="1.3"/>
<circle cx="154.6" cy="85.5" r=".4" fill="#fff" stroke="#000" stroke-width=".21"/>
<path d="M153.9 88.1h1.3" fill="none" stroke="#000" stroke-width="1.3"/>
<circle cx="154.6" cy="88.1" r=".4" fill="#fff" stroke="#000" stroke-width=".21"/>
<path d="M128.7 83h1.5" fill="none" stroke="#000" stroke-width="1.5"/>
<circle cx="129.5" cy="83" r=".51" fill="#fff" stroke="#000" stroke-width=".21"/>
<path d="M128.7 85.5h1.5" fill="none" stroke="#000" stroke-width="1.5"/>
<circle cx="129.5" cy="85.5" r=".51" fill="#fff" stroke="#000" stroke-width=".21"/>
<path d="M141.9 94v1.3" fill="none" stroke="#000" stroke-width="1.3"/>
<circle cx="141.9" cy="94.6" r=".4" fill="#fff" stroke="#000" stroke-width=".21"/>
<path d="M139.4 94v1.3" fill="none" stroke="#000" stroke-width="1.3"/>
<circle cx="139.4" cy="94.6" r=".4" fill="#fff" stroke="#000" stroke-width=".21"/>
<path d="M131.8 94v1.3" fill="none" stroke="#000" stroke-width="1.3"/>
<circle cx="131.8" cy="94.6" r=".4" fill="#fff" stroke="#000" stroke-width=".21"/>
<path d="M126.7 94v1.3" fill="none" stroke="#000" stroke-width="1.3"/>
<circle cx="126.7" cy="94.6" r=".4" fill="#fff" stroke="#000" stroke-width=".21"/>
<circle cx="158.4" cy="62.4" r=".71" fill="#000" stroke="#000" stroke-width=".21"/>
<circle cx="158.4" cy="62.4" r=".4" fill="#fff" stroke="#000" stroke-width=".21"/>
<circle cx="158.4" cy="59.8" r=".71" fill="#000" stroke="#000" stroke-width=".21"/>
<circle cx="158.4" cy="59.8" r=".4" fill="#fff" stroke="#000" stroke-width=".21"/>
<circle cx="133.6" cy="80.5" r=".71" fill="#000" stroke="#000" stroke-width=".21"/>
<circle cx="133.6" cy="80.5" r=".4" fill="#fff" stroke="#000" stroke-width=".21"/>
<circle cx="133.6" cy="85.5" r=".71" fill="#000" stroke="#000" stroke-width=".21"/>
<circle cx="133.6" cy="85.5" r=".4" fill="#fff" stroke="#000" stroke-width=".21"/>
<circle cx="136.1" cy="70.3" r=".66" fill="#000" stroke="#000" stroke-width=".21"/>
<circle cx="136.1" cy="70.3" r=".4" fill="#fff" stroke="#000" stroke-width=".21"/>
<circle cx="136.1" cy="72.8" r=".66" fill="#000" stroke="#000" stroke-width=".21"/>
<circle cx="136.1" cy="72.8" r=".4" fill="#fff" stroke="#000" stroke-width=".21"/>
<circle cx="143.8" cy="72.8" r=".66" fill="#000" stroke="#000" stroke-width=".21"/>
<circle cx="143.8" cy="72.8" r=".4" fill="#fff" stroke="#000" stroke-width=".21"/>
<circle cx="143.8" cy="70.3" r=".66" fill="#000" stroke="#000" stroke-width=".21"/>
<circle cx="143.8" cy="70.3" r=".4" fill="#fff" stroke="#000" stroke-width=".21"/>
<circle cx="136.1" cy="75.4" r=".66" fill="#000" stroke="#000" stroke-width=".21"/>
<circle cx="136.1" cy="75.4" r=".4" fill="#fff" stroke="#000" stroke-width=".21"/>
<circle cx="136.1" cy="77.9" r=".66" fill="#000" stroke="#000" stroke-width=".21"/>
<circle cx="136.1" cy="77.9" r=".4" fill="#fff" stroke="#000" stroke-width=".21"/>
<circle cx="143.8" cy="75.4" r=".66" fill="#000" stroke="#000" stroke-width=".21"/>
<circle cx="143.8" cy="75.4" r=".4" fill="#fff" stroke="#000" stroke-width=".21"/>
<circle cx="143.8" cy="77.9" r=".66" fill="#000" stroke="#000" stroke-width=".21"/>
<circle cx="143.8" cy="77.9" r=".4" fill="#fff" stroke="#000" stroke-width=".21"/>
<circle cx="152" cy="67.1" r=".71" fill="#000" stroke="#000" stroke-width=".21"/>
<circle cx="152" cy="67.1" r=".4" fill="#fff" stroke="#000" stroke-width=".21"/>
<circle cx="146.9" cy="67.1" r=".71" fill="#000" stroke="#000" stroke-width=".21"/>
<circle cx="146.9" cy="67.1" r=".4" fill="#fff" stroke="#000" stroke-width=".21"/>
<path d="M146.3 70.3h1.3" fill="none" stroke="#000" stroke-width="1.3"/>
<circle cx="146.9" cy="70.3" r=".4" fill="#fff" stroke="#000" stroke-width=".21"/>
<path d="M146.3 72.8h1.3" fill="none" stroke="#000" stroke-width="1.3"/>
<circle cx="146.9" cy="72.8" r=".4" fill="#fff" stroke="#000" stroke-width=".21"/>
<path d="M153.9 72.8h1.3" fill="none" stroke="#000" stroke-width="1.3"/>
<circle cx="154.6" cy="72.8" r=".4" fill="#fff" stroke="#000" stroke-width=".21"/>
<path d="M153.9 70.3h1.3" fill="none" stroke="#000" stroke-width="1.3"/>
<circle cx="154.6" cy="70.3" r=".4" fill="#fff" stroke="#000" stroke-width=".21"/>
<path d="M146.3 75.4h1.3" fill="none" stroke="#000" stroke-width="1.3"/>
<circle cx="146.9" cy="75.4" r=".4" fill="#fff" stroke="#000" stroke-width=".21"/>
<path d="M146.3 77.9h1.3" fill="none" stroke="#000" stroke-width="1.3"/>
<circle cx="146.9" cy="77.9" r=".4" fill="#fff" stroke="#000" stroke-width=".21"/>
<path d="M153.9 75.4h1.3" fill="none" stroke="#000" stroke-width="1.3"/>
<circle cx="154.6" cy="75.4" r=".4" fill="#fff" stroke="#000" stroke-width=".21"/>
<path d="M153.9 77.9h1.3" fill="none" stroke="#000" stroke-width="1.3"/>
<circle cx="154.6" cy="77.9" r=".4" fill="#fff" stroke="#000" stroke-width=".21"/>
<path d="M128.7 72.8h1.5" fill="none" stroke="#000" stroke-width="1.5"/>
<circle cx="129.5" cy="72.8" r=".51" fill="#fff" stroke="#000" stroke-width=".21"/>
<path d="M128.7 75.4h1.5" fill="none" stroke="#000" stroke-width="1.5"/>
<circle cx="129.5" cy="75.4" r=".51" fill="#fff" stroke="#000" stroke-width=".21"/>
<path d="M141.9 66.7v1.3" fill="none" stroke="#000" stroke-width="1.3"/>
<circle cx="141.9" cy="67.3" r=".4" fill="#fff" stroke="#000" stroke-width=".21"/>
<path d="M139.4 66.7v1.3" fill="none" stroke="#000" stroke-width="1.3"/>
<circle cx="139.4" cy="67.3" r=".4" fill="#fff" stroke="#000" stroke-width=".21"/>
<path d="M131.8 66.7v1.3" fill="none" stroke="#000" stroke-width="1.3"/>
<circle cx="131.8" cy="67.3" r=".4" fill="#fff" stroke="#000" stroke-width=".21"/>
<path d="M126.7 66.7v1.3" fill="none" stroke="#000" stroke-width="1.3"/>
<circle cx="126.7" cy="67.3" r=".4" fill="#fff" stroke="#000" stroke-width=".21"/>
<circle cx="161.9" cy="62.4" r=".71" fill="#000" stroke="#000" stroke-width=".21"/>
<circle cx="161.9" cy="62.4" r=".4" fill="#fff" stroke="#000" stroke-width=".21"/>
<circle cx="161.9" cy="59.8" r=".71" fill="#000" stroke="#000" stroke-width=".21"/>
<circle cx="161.9" cy="59.8" r=".4" fill="#fff" stroke="#000" stroke-width=".21"/>
<circle cx="133.6" cy="70.3" r=".71" fill="#000" stroke="#000" stroke-width=".21"/>
<circle cx="133.6" cy="70.3" r=".4" fill="#fff" stroke="#000" stroke-width=".21"/>
<circle cx="133.6" cy="75.4" r=".71" fill="#000" stroke="#000" stroke-width=".21"/>
<circle cx="133.6" cy="75.4" r=".4" fill="#fff" stroke="#000" stroke-width=".21"/>
<path d="M170 85.5h1.5" fill="none" stroke="#000" stroke-width="1.5"/>
<circle cx="170.8" cy="85.5" r=".51" fill="#fff" stroke="#000" stroke-width=".21"/>
<path d="M170 88.1h1.5" fill="none" stroke="#000" stroke-width="1.5"/>
<circle cx="170.8" cy="88.1" r=".51" fill="#fff" stroke="#000" stroke-width=".21"/>
<path d="M170 90.6h1.5" fill="none" stroke="#000" stroke-width="1.5"/>
<circle cx="170.8" cy="90.6" r=".51" fill="#fff" stroke="#000" stroke-width=".21"/>
<path d="M170 83h1.5" fill="none" stroke="#000" stroke-width="1.5"/>
<circle cx="170.8" cy="83" r=".51" fill="#fff" stroke="#000" stroke-width=".21"/>
<path d="M170 80.5h1.5" fill="none" stroke="#000" stroke-width="1.5"/>
<circle cx="170.8" cy="80.5" r=".51" fill="#fff" stroke="#000" stroke-width=".21"/>
<path d="M170 77.9h1.5" fill="none" stroke="#000" stroke-width="1.5"/>
<circle cx="170.8" cy="77.9" r=".51" fill="#fff" stroke="#000" stroke-width=".21"/>
<path d="M170 75.4h1.5" fill="none" stroke="#000" stroke-width="1.5"/>
<circle cx="170.8" cy="75.4" r=".51" fill="#fff" stroke="#000" stroke-width=".21"/>
<path d="M170 72.8h1.5" fill="none" stroke="#000" stroke-width="1.5"/>
<circle cx="170.8" cy="72.8" r=".51" fill="#fff" stroke="#000" stroke-width=".21"/>
<path d="M170 70.3h1.5" fill="none" stroke="#000" stroke-width="1.5"/>
<circle cx="170.8" cy="70.3" r=".51" fill="#fff" stroke="#000" stroke-width=".21"/>
<path d="M170 67.8h1.5" fill="none" stroke="#000" stroke-width="1.5"/>
<circle cx="170.8" cy="67.8" r=".51" fill="#fff" stroke="#000" stroke-width=".21"/>
<path d="M170 59.8h1.5" fill="none" stroke="#000" stroke-width="1.5"/>
<circle cx="170.8" cy="59.8" r=".51" fill="#fff" stroke="#000" stroke-width=".21"/>
<path d="M170 62.4h1.5" fill="none" stroke="#000" stroke-width="1.5"/>
<circle cx="170.8" cy="62.4" r=".51" fill="#fff" stroke="#000" stroke-width=".21"/>
<circle cx="143.8" cy="115.7" r=".71" fill="#000" stroke="#000" stroke-width=".21"/>
<circle cx="143.8" cy="115.7" r=".4" fill="#fff" stroke="#000" stroke-width=".21"/>
<circle cx="143.8" cy="110.6" r=".71" fill="#000" stroke="#000" stroke-width=".21"/>
<circle cx="143.8" cy="110.6" r=".4" fill="#fff" stroke="#000" stroke-width=".21"/>
<path d="M146.3 110.6h1.3" fill="none" stroke="#000" stroke-width="1.3"/>
<circle cx="146.9" cy="110.6" r=".4" fill="#fff" stroke="#000" stroke-width=".21"/>
<path d="M146.3 113.2h1.3" fill="none" stroke="#000" stroke-width="1.3"/>
<circle cx="146.9" cy="113.2" r=".4" fill="#fff" stroke="#000" stroke-width=".21"/>
<path d="M153.9 113.2h1.3" fill="none" stroke="#000" stroke-width="1.3"/>
<circle cx="154.6" cy="113.2" r=".4" fill="#fff" stroke="#000" stroke-width=".21"/>
<path d="M153.9 110.6h1.3" fill="none" stroke="#000" stroke-width="1.3"/>
<circle cx="154.6" cy="110.6" r=".4" fill="#fff" stroke="#000" stroke-width=".21"/>
<path d="M146.3 115.7h1.3" fill="none" stroke="#000" stroke-width="1.3"/>
<circle cx="146.9" cy="115.7" r=".4" fill="#fff" stroke="#000" stroke-width=".21"/>
<path d="M146.3 118.2h1.3" fill="none" stroke="#000" stroke-width="1.3"/>
<circle cx="146.9" cy="118.2" r=".4" fill="#fff" stroke="#000" stroke-width=".21"/>
<path d="M153.9 115.7h1.3" fill="none" stroke="#000" stroke-width="1.3"/>
<circle cx="154.6" cy="115.7" r=".4" fill="#fff" stroke="#000" stroke-width=".21"/>
<path d="M153.9 118.2h1.3" fill="none" stroke="#000" stroke-width="1.3"/>
<circle cx="154.6" cy="118.2" r=".4" fill="#fff" stroke="#000" stroke-width=".21"/>
<circle cx="143.8" cy="105.5" r=".71" fill="#000" stroke="#000" stroke-width=".21"/>
<circle cx="143.8" cy="105.5" r=".4" fill="#fff" stroke="#000" stroke-width=".21"/>
<circle cx="143.8" cy="100.5" r=".71" fill="#000" stroke="#000" stroke-width=".21"/>
<circle cx="143.8" cy="100.5" r=".4" fill="#fff" stroke="#000" stroke-width=".21"/>
<path d="M146.3 100.5h1.3" fill="none" stroke="#000" stroke-width="1.3"/>
<circle cx="146.9" cy="100.5" r=".4" fill="#fff" stroke="#000" stroke-width=".21"/>
<path d="M146.3 103h1.3" fill="none" stroke="#000" stroke-width="1.3"/>
<circle cx="146.9" cy="103" r=".4" fill="#fff" stroke="#000" stroke-width=".21"/>
<path d="M153.9 103h1.3" fill="none" stroke="#000" stroke-width="1.3"/>
<circle cx="154.6" cy="103" r=".4" fill="#fff" stroke="#000" stroke-width=".21"/>
<path d="M153.9 100.5h1.3" fill="none" stroke="#000" stroke-width="1.3"/>
<circle cx="154.6" cy="100.5" r=".4" fill="#fff" stroke="#000" stroke-width=".21"/>
<path d="M146.3 105.5h1.3" fill="none" stroke="#000" stroke-width="1.3"/>
<circle cx="146.9" cy="105.5" r=".4" fill="#fff" stroke="#000" stroke-width=".21"/>
<path d="M146.3 108.1h1.3" fill="none" stroke="#000" stroke-width="1.3"/>
<circle cx="146.9" cy="108.1" r=".4" fill="#fff" stroke="#000" stroke-width=".21"/>
<path d="M153.9 105.5h1.3" fill="none" stroke="#000" stroke-width="1.3"/>
<circle cx="154.6" cy="105.5" r=".4" fill="#fff" stroke="#000" stroke-width=".21"/>
<path d="M153.9 108.1h1.3" fill="none" stroke="#000" stroke-width="1.3"/>
<circle cx="154.6" cy="108.1" r=".4" fill="#fff" stroke="#000" stroke-width=".21"/>
<path d="M128.7 110.6h1.5" fill="none" stroke="#000" stroke-width="1.5"/>
<circle cx="129.5" cy="110.6" r=".51" fill="#fff" stroke="#000" stroke-width=".21"/>
<path d="M128.7 113.2h1.5" fill="none" stroke="#000" stroke-width="1.5"/>
<circle cx="129.5" cy="113.2" r=".51" fill="#fff" stroke="#000" stroke-width=".21"/>
<path d="M128.7 115.7h1.5" fill="none" stroke="#000" stroke-width="1.5"/>
<circle cx="129.5" cy="115.7" r=".51" fill="#fff" stroke="#000" stroke-width=".21"/>
<path d="M128.7 100.5h1.5" fill="none" stroke="#000" stroke-width="1.5"/>
<circle cx="129.5" cy="100.5" r=".51" fill="#fff" stroke="#000" stroke-width=".21"/>
<path d="M128.7 103h1.5" fill="none" stroke="#000" stroke-width="1.5"/>
<circle cx="129.5" cy="103" r=".51" fill="#fff" stroke="#000" stroke-width=".21"/>
<path d="M128.7 105.5h1.5" fill="none" stroke="#000" stroke-width="1.5"/>
<circle cx="129.5" cy="105.5" r=".51" fill="#fff" stroke="#000" stroke-width=".21"/>
<path d="M146.3 49.9v1.5" fill="none" stroke="#000" stroke-width="1.5"/>
<circle cx="146.3" cy="50.6" r=".51" fill="#fff" stroke="#000" stroke-width=".21"/>
<path d="M148.8 49.9v1.5" fill="none" stroke="#000" stroke-width="1.5"/>
<circle cx="148.8" cy="50.6" r=".51" fill="#fff" stroke="#000" stroke-width=".21"/>
<circle cx="148.8" cy="56.7" r=".76" fill="#000" stroke="#000" stroke-width=".21"/>
<circle cx="148.8" cy="56.7" r=".38" fill="#fff" stroke="#000" stroke-width=".21"/>
<circle cx="148.8" cy="62.4" r=".76" fill="#000" stroke="#000" stroke-width=".21"/>
<circle cx="148.8" cy="62.4" r=".38" fill="#fff" stroke="#000" stroke-width=".21"/>
<circle cx="161.9" cy="72.8" r=".76" fill="#000" stroke="#000" stroke-width=".21"/>
<circle cx="161.9" cy="72.8" r=".38" fill="#fff" stroke="#000" stroke-width=".21"/>
<circle cx="161.9" cy="92.8" r=".76" fill="#000" stroke="#000" stroke-width=".21"/>
<circle cx="161.9" cy="92.8" r=".38" fill="#fff" stroke="#000" stroke-width=".21"/>
<circle cx="161.9" cy="70.6" r=".76" fill="#000" stroke="#000" stroke-width=".21"/>
<circle cx="161.9" cy="70.6" r=".38" fill="#fff" stroke="#000" stroke-width=".21"/>
<circle cx="161.9" cy="65.2" r=".76" fill="#000" stroke="#000" stroke-width=".21"/>
<circle cx="161.9" cy="65.2" r=".38" fill="#fff" stroke="#000" stroke-width=".21"/>
<circle cx="164.7" cy="57.3" r=".76" fill="#000" stroke="#000" stroke-width=".21"/>
<circle cx="164.7" cy="57.3" r=".38" fill="#fff" stroke="#000" stroke-width=".21"/>
<circle cx="164.7" cy="65.2" r=".76" fill="#000" stroke="#000" stroke-width=".21"/>
<circle cx="164.7" cy="65.2" r=".38" fill="#fff" stroke="#000" stroke-width=".21"/>
<circle cx="164.7" cy="67.8" r=".76" fill="#000" stroke="#000" stroke-width=".21"/>
<circle cx="164.7" cy="67.8" r=".38" fill="#fff" stroke="#000" stroke-width=".21"/>
<circle cx="164.7" cy="72.8" r=".76" fill="#000" stroke="#000" stroke-width=".21"/>
<circle cx="164.7" cy="72.8" r=".38" fill="#fff" stroke="#000" stroke-width=".21"/>
<circle cx="157.4" cy="83" r=".76" fill="#000" stroke="#000" stroke-width=".21"/>
<circle cx="157.4" cy="83" r=".38" fill="#fff" stroke="#000" stroke-width=".21"/>
<circle cx="157.4" cy="72.8" r=".76" fill="#000" stroke="#000" stroke-width=".21"/>
<circle cx="157.4" cy="72.8" r=".38" fill="#fff" stroke="#000" stroke-width=".21"/>
<circle cx="168.5" cy="95.4" r=".76" fill="#000" stroke="#000" stroke-width=".21"/>
<circle cx="168.5" cy="95.4" r=".38" fill="#fff" stroke="#000" stroke-width=".21"/>
<circle cx="168.5" cy="105.5" r=".76" fill="#000" stroke="#000" stroke-width=".21"/>
<circle cx="168.5" cy="105.5" r=".38" fill="#fff" stroke="#000" stroke-width=".21"/>
<circle cx="168.5" cy="110.6" r=".76" fill="#000" stroke="#000" stroke-width=".21"/>
<circle cx="168.5" cy="110.6" r=".38" fill="#fff" stroke="#000" stroke-width=".21"/>
<circle cx="168.5" cy="115.7" r=".76" fill="#000" stroke="#000" stroke-width=".21"/>
<circle cx="168.5" cy="115.7" r=".38" fill="#fff" stroke="#000" stroke-width=".21"/>
<circle cx="159.6" cy="88.1" r=".76" fill="#000" stroke="#000" stroke-width=".21"/>
<circle cx="159.6" cy="88.1" r=".38" fill="#fff" stroke="#000" stroke-width=".21"/>
<circle cx="159.6" cy="77.9" r=".76" fill="#000" stroke="#000" stroke-width=".21"/>
<circle cx="159.6" cy="77.9" r=".38" fill="#fff" stroke="#000" stroke-width=".21"/>
<circle cx="157.4" cy="88.1" r=".76" fill="#000" stroke="#000" stroke-width=".21"/>
<circle cx="157.4" cy="88.1" r=".38" fill="#fff" stroke="#000" stroke-width=".21"/>
<circle cx="157.4" cy="103" r=".76" fill="#000" stroke="#000" stroke-width=".21"/>
<circle cx="157.4" cy="103" r=".38" fill="#fff" stroke="#000" stroke-width=".21"/>
<circle cx="159.6" cy="103" r=".76" fill="#000" stroke="#000" stroke-width=".21"/>
<circle cx="159.6" cy="103" r=".38" fill="#fff" stroke="#000" stroke-width=".21"/>
<circle cx="159.6" cy="113.2" r=".76" fill="#000" stroke="#000" stroke-width=".21"/>
<circle cx="159.6" cy="113.2" r=".38" fill="#fff" stroke="#000" stroke-width=".21"/>
<circle cx="166.3" cy="80.5" r=".76" fill="#000" stroke="#000" stroke-width=".21"/>
<circle cx="166.3" cy="80.5" r=".38" fill="#fff" stroke="#000" stroke-width=".21"/>
<circle cx="166" cy="115.7" r=".76" fill="#000" stroke="#000" stroke-width=".21"/>
<circle cx="166" cy="115.7" r=".38" fill="#fff" stroke="#000" stroke-width=".21"/>
<circle cx="164.1" cy="77.9" r=".76" fill="#000" stroke="#000" stroke-width=".21"/>
<circle cx="164.1" cy="77.9" r=".38" fill="#fff" stroke="#000" stroke-width=".21"/>
<circle cx="164.1" cy="105.5" r=".76" fill="#000" stroke="#000" stroke-width=".21"/>
<circle cx="164.1" cy="105.5" r=".38" fill="#fff" stroke="#000" stroke-width=".21"/>
<g fill="none" stroke="#000" stroke-width=".21">
<path d="M122.8 44.3h52.4v100h-52.4z"/>
<circle cx="129.3" cy="50.7" r="1.61"/>
</g>
<circle cx="129.3" cy="50.7" r="1.61" fill="#fff" stroke="#000" stroke-width=".21"/>
<circle cx="166.4" cy="50.7" r="1.61" fill="none" stroke="#000" stroke-width=".21"/>
<circle cx="166.4" cy="50.7" r="1.61" fill="#fff" stroke="#000" stroke-width=".21"/>
<circle cx="129.3" cy="137.8" r="1.61" fill="none" stroke="#000" stroke-width=".21"/>
<circle cx="129.3" cy="137.8" r="1.61" fill="#fff" stroke="#000" stroke-width=".21"/>
<circle cx="166.4" cy="137.8" r="1.61" fill="none" stroke="#000" stroke-width=".21"/>
<circle cx="166.4" cy="137.8" r="1.61" fill="#fff" stroke="#000" stroke-width=".21"/>
<g fill="none" stroke="#000" stroke-width=".21">
<path d="M22.5 18.9h252.7v171.4h-252.7zM64.6 15.1v3.8M106.7 15.1v3.8M148.8 15.1v3.8M191 15.1v3.8M233.1 15.1v3.8M18.7 61.7h3.8M275.2 61.7h3.8M18.7 104.6h3.8M275.2 104.6h3.8M18.7 147.4h3.8M275.2 147.4h3.8"/>
<path d="M233.9 170v20.3M233.9 175h41.3M235.9 177.2l.6 1.6 .5-1.6M237.5 177.2h.8M238.3 176.4l-.4 .1-.1 .3v2M239.9 176.4v2.4l-.8-.1-.2-.2v-1.1l.2-.2h.8M240.7 179h1M243.3 177.2h-.7l-.2 .4 .1 1 .8 .2M244.1 177.4l.5-.2a.92 .92 0 0 1 .2 1.5l-.4 .1-.3-.2-.1-.4zM245.9 178.8v-1.6l.9 .1 .1 1.5M247.6 177.2h.8M247.9 176.4v2.1l.5 .3"/>
<path d="M249.9 177.5v-.3h-.7v1.6M250.7 177.4l.4-.2a.92 .92 0 0 1 .2 1.5l-.3 .1-.3-.2-.2-.4zM252.4 176.4v2l.1 .2 .3 .2M253.5 176.4v2.1l.4 .3M254.6 178h1a.55 .55 0 0 0-.3-.8 .55 .55 0 0 0-.7 .5l.1 .9 .9 .2M257.2 177.5v-.3h-.7v1.6M257.8 179h1M259.5 176.4l.1 .2zM259.5 177.2v1.6M260.5 177.4l.5-.2a.92 .92 0 0 1 .1 1.5l-.3 .1-.4-.4zM275.2 170h-95.2v20.3M64.6 190.3v3.8"/>
<path d="M106.7 190.3v3.8M148.8 190.3v3.8M191 190.3v3.8M233.1 190.3v3.8M233.9 185.2h41.3M233.9 180.1h41.3M235.9 182.2l.6-.5v2.2M235.9 183.9h1.2M239.7 183.7l.1 .2zM240.8 181.9l.1-.1a.88 .88 0 0 1 .8 1.2l-.1 .3a.51 .51 0 0 1-.5 .6 .51 .51 0 0 1-.5-.6l-.1-.8zM241.6 182.2l-1 1.2M242.4 182v-.3h1.2l-.6 2.2"/>
<path d="M244.3 183.7l.1 .2zM245.1 182.2a.58 .58 0 0 1 .9-.4 .58 .58 0 0 1 .1 .9l-1 1.2h1.2M247.3 181.9l.2-.1a.88 .88 0 0 1 .7 1.2 .61 .61 0 0 1-.6 .9 .61 .61 0 0 1-.5-.9v-.5zM248.1 182.2l-.9 1.2M250 182.2a.58 .58 0 0 1 .8-.4 .58 .58 0 0 1 .2 .9l-1 1.2h1.2M251.9 182.2a.58 .58 0 0 1 .9-.4 .58 .58 0 0 1 .1 .9l-1 1.2h1.2M253.9 182.6l.1 .1zM253.9 183.6l.1 .1zM254.7 181.7h.8a.48 .48 0 0 1 .4 .5 .48 .48 0 0 1-.4 .5h-.5M255.3 182.7a.58 .58 0 0 1 .6 .6 .58 .58 0 0 1-.6 .6h-.6M256.7 181.7h.7a.48 .48 0 0 1 .5 .5 .48 .48 0 0 1-.5 .5h-.5M257.3 182.7a.58 .58 0 0 1 .5 .6 .58 .58 0 0 1-.5 .6h-.6"/>
<path d="M265 185.2v5.1"/>
<circle cx="238.4" cy="182.2" r=".47"/>
<circle cx="238.4" cy="183.3" r=".59"/>
</g>
<path d="M18.7 15.1h260.3v179h-260.3z" fill="none" stroke="#000" stroke-width=".32"/>
<use href="#words"/>
</svg>
